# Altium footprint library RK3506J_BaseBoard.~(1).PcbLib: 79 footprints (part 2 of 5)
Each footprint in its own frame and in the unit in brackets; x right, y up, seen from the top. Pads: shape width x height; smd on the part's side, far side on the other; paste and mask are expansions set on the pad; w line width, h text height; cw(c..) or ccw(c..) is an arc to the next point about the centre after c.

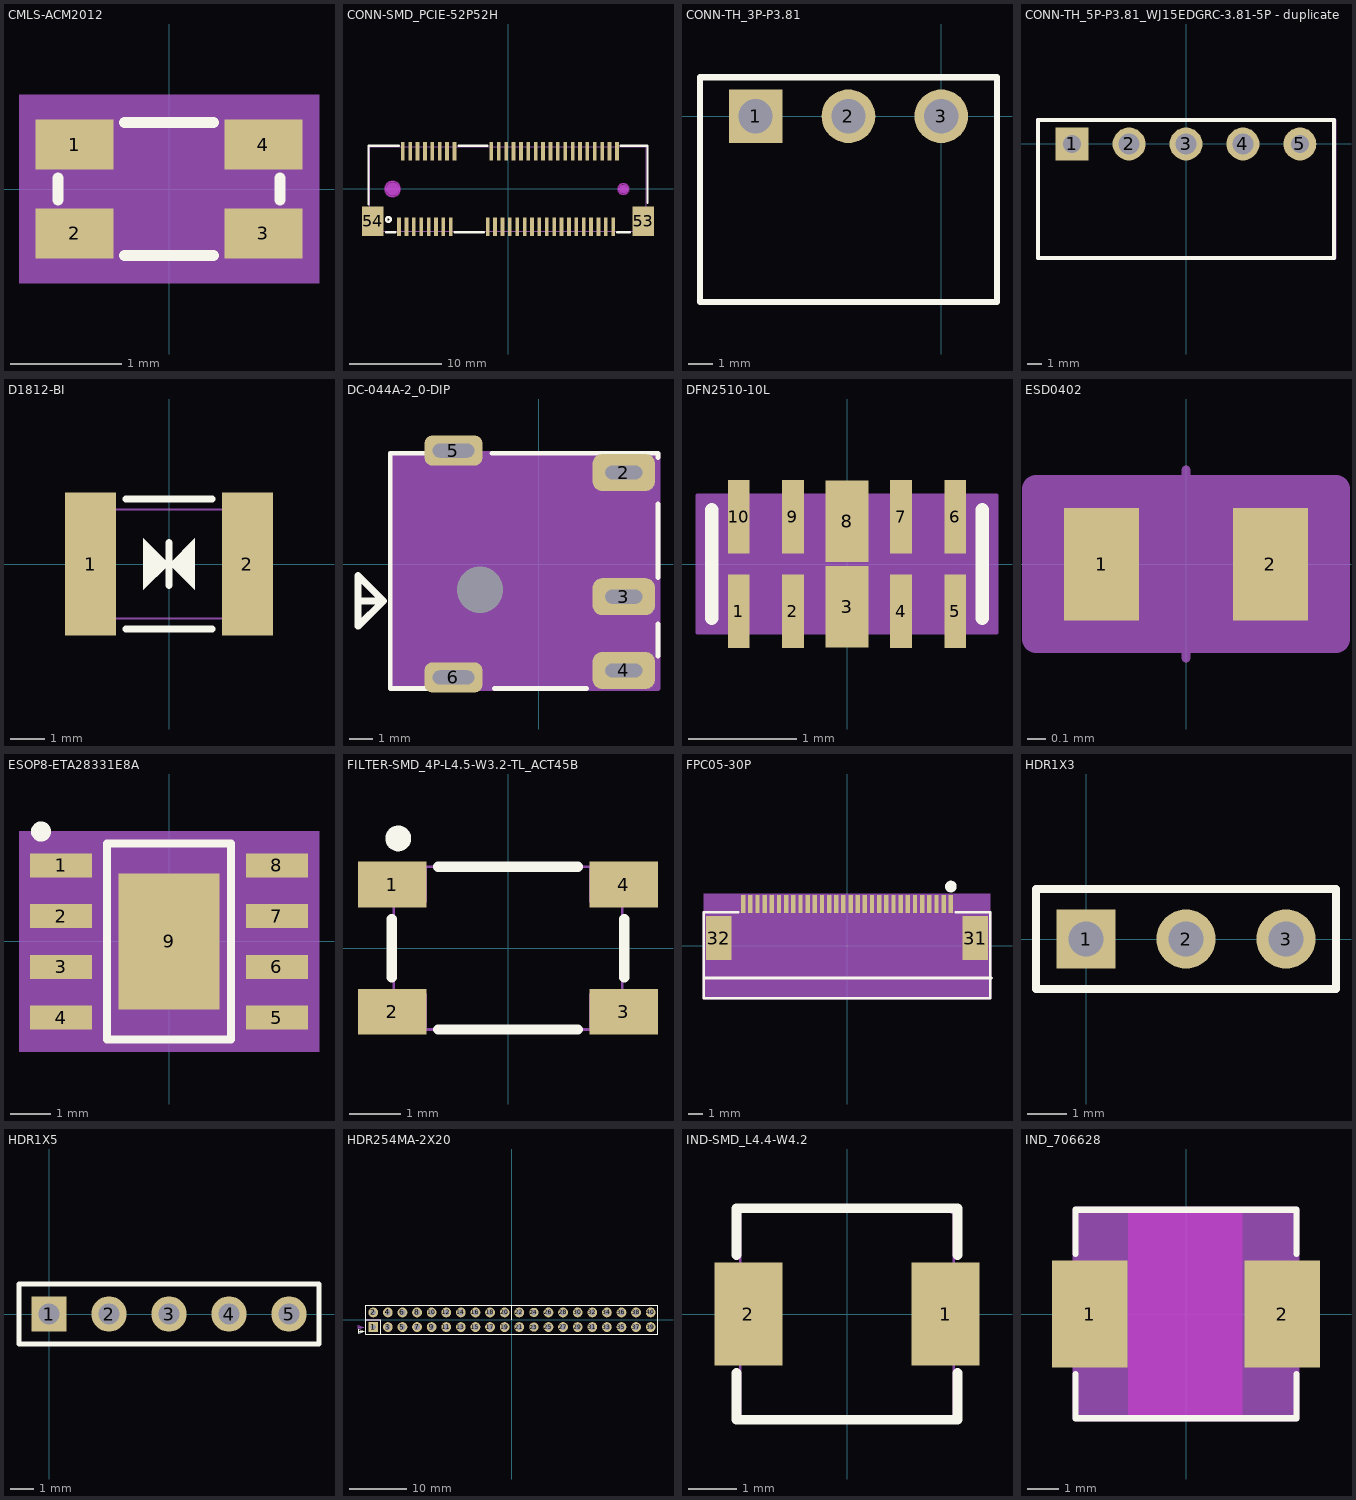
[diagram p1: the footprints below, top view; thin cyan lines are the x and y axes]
## CMLS-ACM2012 [mm]
pads (4):
  rect 0.7x0.45 smd: 1(-0.85,0.4) 2(-0.85,-0.4) 3(0.85,-0.4) 4(0.85,0.4)
Top Overlay:
  lines w0.1: -1,-0.1 -1,0.1 ; -0.4,-0.6 0.4,-0.6 ; -0.4,0.6 0.4,0.6 ; 1,-0.1 1,0.1
Top 3D Body:
  circle w0.05: c0,0 r0.35
  region: -1.35,-0.85 -1.35,0.85 1.35,0.85 1.35,-0.85
  lines w0.05: -0.5,0 0.5,0 ; 0,-0.5 0,0.5
Top Assembly:
  lines w0.1: -1,-0.6 -1,0.6 1,0.6 1,-0.6 -1,-0.6
Top Component Outline:
  lines w0.001: -1.1,-0.7 -1.1,0.7 1.1,0.7 1.1,-0.7 -1.1,-0.7
Top Courtyard:
  dashed: -1.35,-0.85 -1.35,0.85 1.35,0.85 1.35,-0.85
Mechanical 15:
  text "1" at -0.85,0.654 h0.76
  text "2" at -0.85,-0.146 h0.76
  text "3" at 0.85,-0.146 h0.76
  text "4" at 0.85,0.654 h0.76
3D body: height 3.81, standoff 0, extent -1.35,-0.85 1.35,0.85

## CONN-SMD_PCIE-52P52H [mm]
pads (54):
  rect 0.4x2 smd: 1(-11.8,-4.1) 2(-11.4,4.1) 3(-11,-4.1) 4(-10.6,4.1) 5(-10.2,-4.1) 6(-9.8,4.1) 7(-9.4,-4.1) 8(-9,4.1) 9(-8.6,-4.1) 10(-8.2,4.1) 11(-7.8,-4.1) 12(-7.4,4.1) 13(-7,-4.1) 14(-6.6,4.1) 15(-6.2,-4.1) 16(-5.8,4.1) 17(-2.2,-4.1) 18(-1.8,4.1) 19(-1.4,-4.1) 20(-1,4.1) 21(-0.6,-4.1) 22(-0.2,4.1) 23(0.2,-4.1) 24(0.6,4.1) 25(1,-4.1) 26(1.4,4.1) 27(1.8,-4.1) 28(2.2,4.1) 29(2.6,-4.1) 30(3,4.1) 31(3.4,-4.1) 32(3.8,4.1) 33(4.2,-4.1) 34(4.6,4.1) 35(5,-4.1) 36(5.4,4.1) 37(5.8,-4.1) 38(6.2,4.1) 39(6.6,-4.1) 40(7,4.1) 41(7.4,-4.1) 42(7.8,4.1) 43(8.2,-4.1) 44(8.6,4.1) 45(9,-4.1) 46(9.4,4.1) 47(9.8,-4.1) 48(10.2,4.1) 49(10.6,-4.1) 50(11,4.1) 51(11.4,-4.1) 52(11.8,4.1)
  rect 2.3x3.2 smd: 53(14.65,-3.5) 54(-14.65,-3.5)
Top Overlay:
  circle w0.254: c-12.954,-3.302 r0.254
  lines w0.254: -15.113,-1.651 -15.113,4.699 -11.831,4.699 ; -13.208,-4.699 -12.231,-4.699 ; -5.769,-4.699 -2.631,-4.699 ; -5.369,4.699 -2.231,4.699 ; 11.831,-4.699 13.208,-4.699 ; 12.231,4.699 15.113,4.699 15.113,-1.524
Keep-Out Layer:
  board cut-out: 13.05,0 13.05,0.11 12.966,0.312 12.811,0.466 12.609,0.55 12.39,0.55 12.188,0.466 12.034,0.312 11.95,0.109 11.95,0 11.95,-0.109 12.034,-0.311 12.188,-0.466 12.39,-0.55 12.609,-0.55 12.811,-0.466 12.966,-0.311 13.05,-0.109 13.05,0
  board cut-out: -11.7,0 -11.701,0.105 -11.756,0.308 -11.861,0.49 -12.01,0.638 -12.192,0.743 -12.395,0.797 -12.605,0.797 -12.808,0.743 -12.99,0.638 -13.139,0.49 -13.245,0.308 -13.3,0.105 -13.3,0 -13.3,-0.105 -13.245,-0.308 -13.139,-0.489 -12.99,-0.638 -12.808,-0.742 -12.605,-0.797 -12.395,-0.797 -12.192,-0.742 -12.01,-0.638 -11.861,-0.489 -11.756,-0.308 -11.701,-0.105 -11.7,0
Keep-Out Layer:
  circle w0.025: c12.5,0 r0.55
  circle w0.254: c12.5,0 r0.55
  circle w0.025: c-12.5,0 r0.8
  circle w0.254: c-12.5,0 r0.8
Mechanical 1:
  circle w0.025: c12.5,0 r0.55
  circle w0.025: c-12.5,0 r0.8
Top Component Outline:
  circle w0.7: c-12.5,0 r0.35
  circle w0.45: c12.5,0 r0.225
Mechanical 15:
  drawing of 59 lines, arcs and shapes, not listed

## CONN-TH_3P-P3.81 [mm]
pads (3):
  rect 2.2x2.2 hole 1.4: 1(-7.62,0)
  round 2.2 hole 1.4: 2(-3.81,0) 3(0,0)
Top Overlay:
  lines w0.254: -9.906,-7.62 -9.906,1.6 2.286,1.6 2.286,-7.62 -9.906,-7.62
Mechanical 15:
  region: -8.02,0.4 -7.22,0.4 -7.22,-0.4 -8.02,-0.4
  region: -4.21,0.4 -3.41,0.4 -3.41,-0.4 -4.21,-0.4
  region: -0.4,0.4 0.4,0.4 0.4,-0.4 -0.4,-0.4
  region: -9.905,-7.55 -9.906,-7.526 -9.941,-7.493 -9.989,-7.493 -10.024,-7.526 -10.025,-7.55 -10.024,-7.574 -9.989,-7.608 -9.941,-7.608 -9.906,-7.574 -9.905,-7.55
  lines w0.051: -9.965,-7.55 -9.965,1.651

## CONN-TH_5P-P3.81_WJ15EDGRC-3.81-5P - duplicate [mm]
pads (5):
  rect 2.2x2.2 hole 1.2: 1(-7.62,0)
  round 2.2 hole 1.4: 2(-3.81,0) 3(0,0) 4(3.81,0)
  round 2.2 hole 1.2: 5(7.62,0)
Top Overlay:
  lines w0.254: -9.906,-7.624 5.842,-7.624 9.906,-7.624 9.906,1.6 -9.906,1.6 -9.906,-7.55
Top Component Outline:
  region: 5.842,-7.497 9.779,-7.497 9.779,1.473 -9.779,1.473 -9.779,-7.55 -9.779,-7.603 -9.853,-7.677 -9.959,-7.677 -10.033,-7.603 -10.033,-7.55 -10.033,1.6 -10.033,1.625 -10.014,1.672 -9.978,1.708 -9.931,1.727 -9.906,1.727 9.906,1.727 9.931,1.727 9.978,1.708 10.014,1.672 10.033,1.625 10.033,1.6 10.033,-7.624 10.033,-7.649 10.014,-7.696 9.978,-7.732 9.931,-7.751 9.906,-7.751 5.842,-7.751 5.789,-7.751 5.715,-7.677 5.715,-7.571 5.789,-7.497 5.842,-7.497
  region: -9.906,-7.497 5.842,-7.497 5.895,-7.497 5.969,-7.571 5.969,-7.677 5.895,-7.751 5.842,-7.751 -9.906,-7.751 -9.959,-7.751 -10.033,-7.677 -10.033,-7.571 -9.959,-7.497 -9.906,-7.497
Mechanical 15:
  region: -9.905,-7.55 -9.906,-7.526 -9.941,-7.493 -9.989,-7.493 -10.024,-7.526 -10.025,-7.55 -10.024,-7.574 -9.989,-7.608 -9.941,-7.608 -9.906,-7.574 -9.905,-7.55
  region: 7.22,0.4 8.02,0.4 8.02,-0.4 7.22,-0.4
  region: 3.41,0.4 4.21,0.4 4.21,-0.4 3.41,-0.4
  region: -0.4,0.4 0.4,0.4 0.4,-0.4 -0.4,-0.4
  region: -4.21,0.4 -3.41,0.4 -3.41,-0.4 -4.21,-0.4
  region: -8.02,0.4 -7.22,0.4 -7.22,-0.4 -8.02,-0.4
  lines w0.051: -9.965,-7.55 -9.965,1.6 9.965,1.6 9.965,-7.55 -9.965,-7.55

## D1812-BI [mm]
pads (2):
  rect 1.5x4.2 smd: 1(-2.305,0) 2(2.305,0)
Top Overlay:
  region: 0,0 -0.762,-0.762 -0.762,0.762
  region: 0,0 0.762,0.762 0.762,-0.762
  lines w0.2: -1.27,-1.905 1.27,-1.905 ; -1.27,1.905 1.27,1.905 ; 0,-0.635 0,0.635
Mechanical 15:
  region: -2.25,1.6 -1.75,1.6 -1.75,-1.6 -2.25,-1.6
  region: 1.75,1.6 2.25,1.6 2.25,-1.6 1.75,-1.6
  region: -2.19,-1.6 -2.191,-1.576 -2.226,-1.542 -2.274,-1.542 -2.309,-1.576 -2.31,-1.6 -2.309,-1.624 -2.274,-1.658 -2.226,-1.658 -2.191,-1.624 -2.19,-1.6
  lines w0.051: -2.25,-1.6 2.25,-1.6 2.25,1.6 -2.25,1.6 -2.25,-1.6

## DC-044A-2_0-DIP [mm]
pads (6):
  round 0 / inner round 1.524 / far side round 2.3 hole 2 unplated: 1(-2.54,-1.115)
  rrect50% 2.7x1.6 hole 0.6 slot 1.6 at 0 deg: 2(3.69,3.965) 3(3.69,-1.415) 4(3.69,-4.615)
  rrect50% 2.5x1.3 hole 0.6 slot 1.8 at 0 deg: 5(-3.69,4.915) 6(-3.69,-4.915)
Top Overlay:
  lines w0.2: -4.928,4.803 -6.428,4.803 -6.428,-5.397 -4.828,-5.397 ; -2.028,4.803 5.172,4.803 5.172,4.602 ; -1.928,-5.397 2.072,-5.397 ; 5.172,-3.998 5.172,-2.598 ; 5.172,-0.598 5.172,2.602
  lines w0.3: -7.828,-1.598 -6.728,-1.598 ; -6.728,-1.598 -7.828,-0.498 -7.828,-2.698 -6.728,-1.598
Top 3D Body:
  region: -6.428,4.803 -6.428,-5.397 5.172,-5.397 5.172,4.803
Top Assembly:
  lines w0.2: -6.428,-5.397 -6.428,4.803 5.172,4.803 5.172,-5.397 -6.428,-5.397
  text "DC-044A-2_5" at -4.828,-3.898 h1.52
  text ".Designator" at 0.43,-0.582 h0.36
Mechanical 15:
  text "6" at -3.428,-5.613 h0.46
  text "5" at -3.428,4.186 h0.46
  text "2" at 3.772,3.236 h0.46
  text "3" at 3.772,-1.963 h0.46
  text "4" at 3.772,-5.364 h0.46
  text "1" at -2.328,-1.963 h0.46
3D body: height 3.81, standoff 0, extent -6.428,-5.397 5.172,4.803

## DFN2510-10L [mm]
pads (10):
  rect 0.2x0.68 smd: 1(-1,-0.437) 2(-0.5,-0.437) 4(0.5,-0.437) 5(1,-0.437) 6(1,0.437) 7(0.5,0.437) 9(-0.5,0.437) 10(-1,0.437)
  rect 0.4x0.75 smd: 3(0,-0.395) 8(0,0.395)
Top Overlay:
  lines w0.127: -1.25,-0.5 -1.25,0.5 ; 1.25,-0.5 1.25,0.5
Top 3D Body:
  region: -1.388,-0.637 1.388,-0.637 1.388,0.637 -1.388,0.637
Top Assembly:
  lines w0.025: -1.388,-0.637 -1.388,0.637 1.388,0.637 1.388,-0.637 -1.388,-0.637
Mechanical 15:
  text "3" at 0.142,-0.395 h0.36
  text "8" at 0.142,0.395 h0.36
  text "5" at 1.142,-0.437 h0.36
  text "6" at 1.142,0.437 h0.36
  text "4" at 0.642,-0.437 h0.36
  text "7" at 0.642,0.437 h0.36
  text "2" at -0.358,-0.437 h0.36
  text "9" at -0.358,0.437 h0.36
  text "1" at -0.858,-0.437 h0.36
  text "10" at -0.716,0.437 h0.36
3D body: height 3.81, standoff 0, extent -1.388,-0.637 1.388,0.637

## ESD0402 [mm]
pads (2):
  rect 0.4x0.6 smd: 1(-0.45,0) 2(0.45,0)
Top 3D Body:
  circle w0.05: c0,0 r0.35
  region: -0.8,0.4 -0.8,-0.4 0.8,-0.4 0.8,0.4
  lines w0.05: -0.5,0 0.5,0 ; 0,-0.5 0,0.5
Top Assembly:
  lines w0.15: -0.8,-0.4 -0.8,0.4 0.8,0.4 0.8,-0.4 -0.8,-0.4
Top Component Outline:
  lines w0.001: -0.525,-0.275 -0.525,0.275 0.525,0.275 0.525,-0.275 -0.525,-0.275
Mechanical 15:
  text "2" at 0.704,0 h0.76
  text "1" at -0.196,0 h0.76
3D body: height 3.81, standoff 0, extent -0.8,-0.4 0.8,0.4

## ESOP8-ETA28331E8A [mm]
pads (9):
  rect 1.55x0.6 smd: 1(-2.7,1.905) 2(-2.7,0.635) 3(-2.7,-0.635) 4(-2.7,-1.905) 5(2.7,-1.905) 6(2.7,-0.635) 7(2.7,0.635) 8(2.7,1.905)
  rect 2.513x3.402 smd: 9(0,0)
Top Overlay:
  circle w0.25: c-3.2,2.75 r0.125
  lines w0.2: -1.55,-2.45 1.55,-2.45 1.55,2.45 -1.55,2.45 -1.55,-2.45
Top 3D Body:
  circle w0.05: c0,0 r0.35
  region: -3.75,-2.75 -3.75,2.75 3.75,2.75 3.75,-2.75
  lines w0.05: -0.5,0 0.5,0 ; 0,-0.5 0,0.5
Top Assembly:
  circle w0.1: c-0.95,1.45 r0.5
  lines w0.1: -1.95,-2.45 1.95,-2.45 1.95,2.45 -1.95,2.45 -1.95,-2.45
Top Component Outline:
  lines w0.001: -2,-2.5 2,-2.5 2,2.5 -2,2.5 -2,-2.5
Top Courtyard:
  dashed: -3.75,-2.75 -3.75,2.75 3.75,2.75 3.75,-2.75
Mechanical 15:
  text "3" at -2.7,-0.889 h0.76
  text "4" at -2.7,-2.159 h0.76
  text "8" at 2.7,1.651 h0.76
  text "6" at 2.7,-0.889 h0.76
  text "1" at -2.7,1.651 h0.76
  text "5" at 2.7,-2.159 h0.76
  text "2" at -2.7,0.381 h0.76
  text "9" at 0,-0.254 h0.76
  text "7" at 2.7,0.381 h0.76
3D body: height 3.81, standoff 0, extent -3.75,-2.75 3.75,2.75

## FILTER-SMD_4P-L4.5-W3.2-TL_ACT45B [mm]
pads (4):
  rect 1.35x0.9 smd: 1(-2.275,1.25) 2(-2.275,-1.25) 3(2.275,-1.25) 4(2.275,1.25)
Top Overlay:
  circle w0.254: c-2.159,2.159 r0.127
  lines w0.203: -2.286,-0.569 -2.286,0.569 ; -1.369,-1.6 1.369,-1.6 ; -1.369,1.6 1.369,1.6 ; 2.286,-0.569 2.286,0.569
Mechanical 15:
  region: -2.25,0.9 -2.25,1.6 -1.6,1.6 -1.6,0.9
  region: 1.6,0.9 1.6,1.6 2.25,1.6 2.25,0.9
  region: 1.6,-1.6 1.6,-0.9 2.25,-0.9 2.25,-1.6
  region: -2.25,-1.6 -2.25,-0.9 -1.6,-0.9 -1.6,-1.6
  region: -2.19,1.6 -2.19,1.625 -2.225,1.66 -2.275,1.66 -2.31,1.625 -2.31,1.6 -2.31,1.575 -2.275,1.54 -2.225,1.54 -2.19,1.575 -2.19,1.6
  lines w0.051: -2.25,-1.6 2.25,-1.6 2.25,1.6 -2.25,1.6 -2.25,-1.6

## FPC05-30P [mm]
pads (32):
  rect 0.305x1.27 smd: 1(7.25,2.925) 2(6.75,2.925) 3(6.25,2.925) 4(5.75,2.925) 5(5.25,2.925) 6(4.75,2.925) 7(4.25,2.925) 8(3.75,2.925) 9(3.25,2.925) 10(2.75,2.925) 11(2.25,2.925) 12(1.75,2.925) 13(1.25,2.925) 14(0.75,2.925) 15(0.25,2.925) 16(-0.25,2.925) 17(-0.75,2.925) 18(-1.25,2.925) 19(-1.75,2.925) 20(-2.25,2.925) 21(-2.75,2.925) 22(-3.25,2.925) 23(-3.75,2.925) 24(-4.25,2.925) 25(-4.75,2.925) 26(-5.25,2.925) 27(-5.75,2.925) 28(-6.25,2.925) 29(-6.75,2.925) 30(-7.25,2.925)
  rect 1.803x3.048 smd: 31(8.95,0.55) 32(-8.95,0.55)
Top Overlay:
  circle w0.406: c7.25,4.147 r0.203
  lines w0.2: -10,-2.25 10.1,-2.25 ; -7.6,2.35 -10,2.35 -10,-3.65 10,-3.65 10,2.35 7.6,2.35
Top 3D Body:
  region: -10,-3.65 10,-3.65 10,3.65 -10,3.65
Top Assembly:
  lines w0.2: -10,-2.25 10,-2.25 ; -10,-3.65 10,-3.65 10,2.35 -10,2.35 -10,-3.65
Mechanical 15:
  text "30" at -7.25,2.417 h0.76
  text "32" at -8.95,0.042 h0.76
  text "23" at -3.75,2.417 h0.76
  text "24" at -4.25,2.417 h0.76
  text "19" at -1.75,2.417 h0.76
  text "20" at -2.25,2.417 h0.76
  text "21" at -2.75,2.417 h0.76
  text "22" at -3.25,2.417 h0.76
  text "13" at 1.25,2.417 h0.76
  text "16" at -0.25,2.417 h0.76
  text "31" at 8.95,0.042 h0.76
  text "6" at 4.75,2.671 h0.76
  text "4" at 5.75,2.671 h0.76
  text "10" at 2.75,2.417 h0.76
  text "8" at 3.75,2.671 h0.76
  text "12" at 1.75,2.417 h0.76
  text "11" at 2.25,2.417 h0.76
  text "15" at 0.25,2.417 h0.76
  text "18" at -1.25,2.417 h0.76
  text "17" at -0.75,2.417 h0.76
  text "14" at 0.75,2.417 h0.76
  text "1" at 7.25,2.671 h0.76
  text "2" at 6.75,2.671 h0.76
  text "3" at 6.25,2.671 h0.76
  text "29" at -6.75,2.417 h0.76
  text "9" at 3.25,2.671 h0.76
  text "7" at 4.25,2.671 h0.76
  text "28" at -6.25,2.417 h0.76
  text "25" at -4.75,2.417 h0.76
  text "27" at -5.75,2.417 h0.76
  text "26" at -5.25,2.417 h0.76
  text "5" at 5.25,2.671 h0.76
3D body: height 3.81, standoff 0, extent -10,-3.65 10,3.65

## HDR1X3 [mm]
pads (3):
  rect 1.5x1.5 hole 0.9: 1(0,0)
  round 1.5 hole 0.9: 2(2.54,0) 3(5.08,0)
Top Overlay:
  lines w0.2: -1.27,-1.27 6.35,-1.27 6.35,1.27 -1.27,1.27 -1.27,-1.27

## HDR1X5 [mm]
pads (5):
  rect 1.5x1.5 hole 0.9: 1(0,0)
  round 1.5 hole 0.9: 2(2.54,0) 3(5.08,0) 4(7.62,0) 5(10.16,0)
Top Overlay:
  lines w0.2: -1.27,-1.27 -1.27,1.27 11.43,1.27 11.43,-1.27 -1.27,-1.27

## HDR254MA-2X20 [mm]
pads (40):
  rect 1.7x1.7 / inner round 1.524 / far side rect 1.7x1.7 hole 0.9: 1(-24.13,-1.27)
  round 1.7 / inner round 1.524 / far side round 1.7 hole 0.9: 2(-24.13,1.27) 39(24.13,-1.27) 40(24.13,1.27)
  round 1.7 / inner round 1.524 / far side round 1.7 hole 1: 3(-21.59,-1.27) 4(-21.59,1.27) 5(-19.05,-1.27) 6(-19.05,1.27) 7(-16.51,-1.27) 8(-16.51,1.27) 9(-13.97,-1.27) 10(-13.97,1.27) 11(-11.43,-1.27) 13(-8.89,-1.27) 14(-8.89,1.27) 15(-6.35,-1.27) 16(-6.35,1.27) 17(-3.81,-1.27) 18(-3.81,1.27) 20(-1.27,1.27) 21(1.27,-1.27) 22(1.27,1.27) 25(6.35,-1.27) 26(6.35,1.27) 27(8.89,-1.27) 28(8.89,1.27) 29(11.43,-1.27) 31(13.97,-1.27) 32(13.97,1.27) 33(16.51,-1.27) 34(16.51,1.27) 35(19.05,-1.27) 36(19.05,1.27) 38(21.59,1.27)
  round 1.7 hole 1: 12(-11.43,1.27) 19(-1.27,-1.27) 30(11.43,1.27) 37(21.59,-1.27)
  round 1.6 / inner round 1.524 / far side round 1.7 hole 1: 23(3.81,-1.27) 24(3.81,1.27)
Top Overlay:
  lines w0.2: -26.654,-2.299 -25.654,-2.032 ; -26.654,-2.099 -25.654,-2.032 ; -26.654,-1.899 -25.654,-2.032 ; -25.4,0 -22.86,0 -22.86,-2.54 ; 0,0 0,2.54 ; -25.654,-2.032 -26.654,-1.699 -26.654,-2.365 -25.654,-2.032 ; -25.4,-2.54 -25.4,2.54 25.4,2.54 25.4,-2.54 -25.4,-2.54
Top 3D Body:
  lines w0.025: -25.4,-2.54 -25.4,2.54 25.4,2.54 25.4,-2.54 -25.4,-2.54
Top Assembly:
  lines w0.2: -26.781,-1.537 -25.781,-1.27 ; -26.781,-1.337 -25.781,-1.27 ; -26.781,-1.137 -25.781,-1.27 ; -25.4,0 -22.86,0 -22.86,-2.54 ; 0,0 0,2.54 ; -25.781,-1.27 -26.781,-0.937 -26.781,-1.603 -25.781,-1.27 ; -25.4,-2.54 -25.4,2.54 25.4,2.54 25.4,-2.54 -25.4,-2.54
  text "pn" at -24.45,-1.47 h0.76
Top Courtyard:
  lines w0.025: -25.4,-2.54 -25.4,2.54 25.4,2.54 25.4,-2.54 -25.4,-2.54
Mechanical 15:
  text "30" at 11.11,1.27 h0.4
  text "12" at -11.75,1.27 h0.4
  text "37" at 21.27,-1.27 h0.4
  text "19" at -1.59,-1.27 h0.4
  text "39" at 23.81,-1.27 h0.4
  text "40" at 23.81,1.27 h0.4
  text "24" at 3.49,1.27 h0.4
  text "26" at 6.03,1.27 h0.4
  text "4" at -21.75,1.27 h0.4
  text "6" at -19.21,1.27 h0.4
  text "8" at -16.67,1.27 h0.4
  text "10" at -14.29,1.27 h0.4
  text "11" at -11.75,-1.27 h0.4
  text "13" at -9.21,-1.27 h0.4
  text "15" at -6.67,-1.27 h0.4
  text "17" at -4.13,-1.27 h0.4
  text "14" at -9.21,1.27 h0.4
  text "21" at 0.95,-1.27 h0.4
  text "23" at 3.49,-1.27 h0.4
  text "25" at 6.03,-1.27 h0.4
  text "27" at 8.57,-1.27 h0.4
  text "22" at 0.95,1.27 h0.4
  text "29" at 11.11,-1.27 h0.4
  text "31" at 13.65,-1.27 h0.4
  text "33" at 16.19,-1.27 h0.4
  text "35" at 18.73,-1.27 h0.4
  text "32" at 13.65,1.27 h0.4
  text "18" at -4.13,1.27 h0.4
  text "20" at -1.59,1.27 h0.4
  text "3" at -21.75,-1.27 h0.4
  text "5" at -19.21,-1.27 h0.4
  text "7" at -16.67,-1.27 h0.4
  text "9" at -14.13,-1.27 h0.4
  text "38" at 21.27,1.27 h0.4
  text "36" at 18.73,1.27 h0.4
  text "34" at 16.19,1.27 h0.4
  text "28" at 8.57,1.27 h0.4
  text "16" at -6.67,1.27 h0.4
  text "2" at -24.29,1.27 h0.4
  text "1" at -24.29,-1.27 h0.4

## IND-SMD_L4.4-W4.2 [mm]
pads (2):
  rect 1.4x2.12 smd paste+0 mask+0.051: 1(2.028,0) 2(-2.028,0)
Top Overlay:
  lines w0.203: -2.276,-1.212 -2.276,-2.176 2.276,-2.176 2.276,-1.212 ; -2.276,1.212 -2.276,2.176 2.276,2.176 2.276,1.212
Mechanical 15:
  region: -2.2,1 -1.4,1 -1.4,-1 -2.2,-1
  region: 1.4,1 2.2,1 2.2,-1 1.4,-1
  region: 2.26,2.1 2.26,2.125 2.225,2.16 2.175,2.16 2.14,2.125 2.14,2.1 2.14,2.075 2.175,2.04 2.225,2.04 2.26,2.075 2.26,2.1
  lines w0.051: -2.2,-2.1 2.2,-2.1 2.2,2.1 -2.2,2.1 -2.2,-2.1

## IND_706628 [mm]
pads (2):
  rect 2.4x3.4 smd: 1(-3.05,0) 2(3.05,0)
Top Layer keep-out:
  region: -1.836,3.315 -1.836,-3.315 1.785,-3.315 1.785,3.315
Top Overlay:
  lines w0.2: -3.5,-1.9 -3.5,-3.3 3.5,-3.3 3.5,-1.9 ; -3.5,1.9 -3.5,3.3 3.5,3.3 3.5,1.9
Top 3D Body:
  region: -3.5,-3.3 3.5,-3.3 3.5,3.3 -3.5,3.3
Top Assembly:
  lines w0.2: -3.5,-3.3 -3.5,3.3 3.5,3.3 3.5,-3.3 -3.5,-3.3
Mechanical 15:
  text "1" at -3.05,0.254 h0.64
  text "2" at 3.05,0.254 h0.64
3D body: height 3.81, standoff 0, extent -3.5,-3.3 3.5,3.3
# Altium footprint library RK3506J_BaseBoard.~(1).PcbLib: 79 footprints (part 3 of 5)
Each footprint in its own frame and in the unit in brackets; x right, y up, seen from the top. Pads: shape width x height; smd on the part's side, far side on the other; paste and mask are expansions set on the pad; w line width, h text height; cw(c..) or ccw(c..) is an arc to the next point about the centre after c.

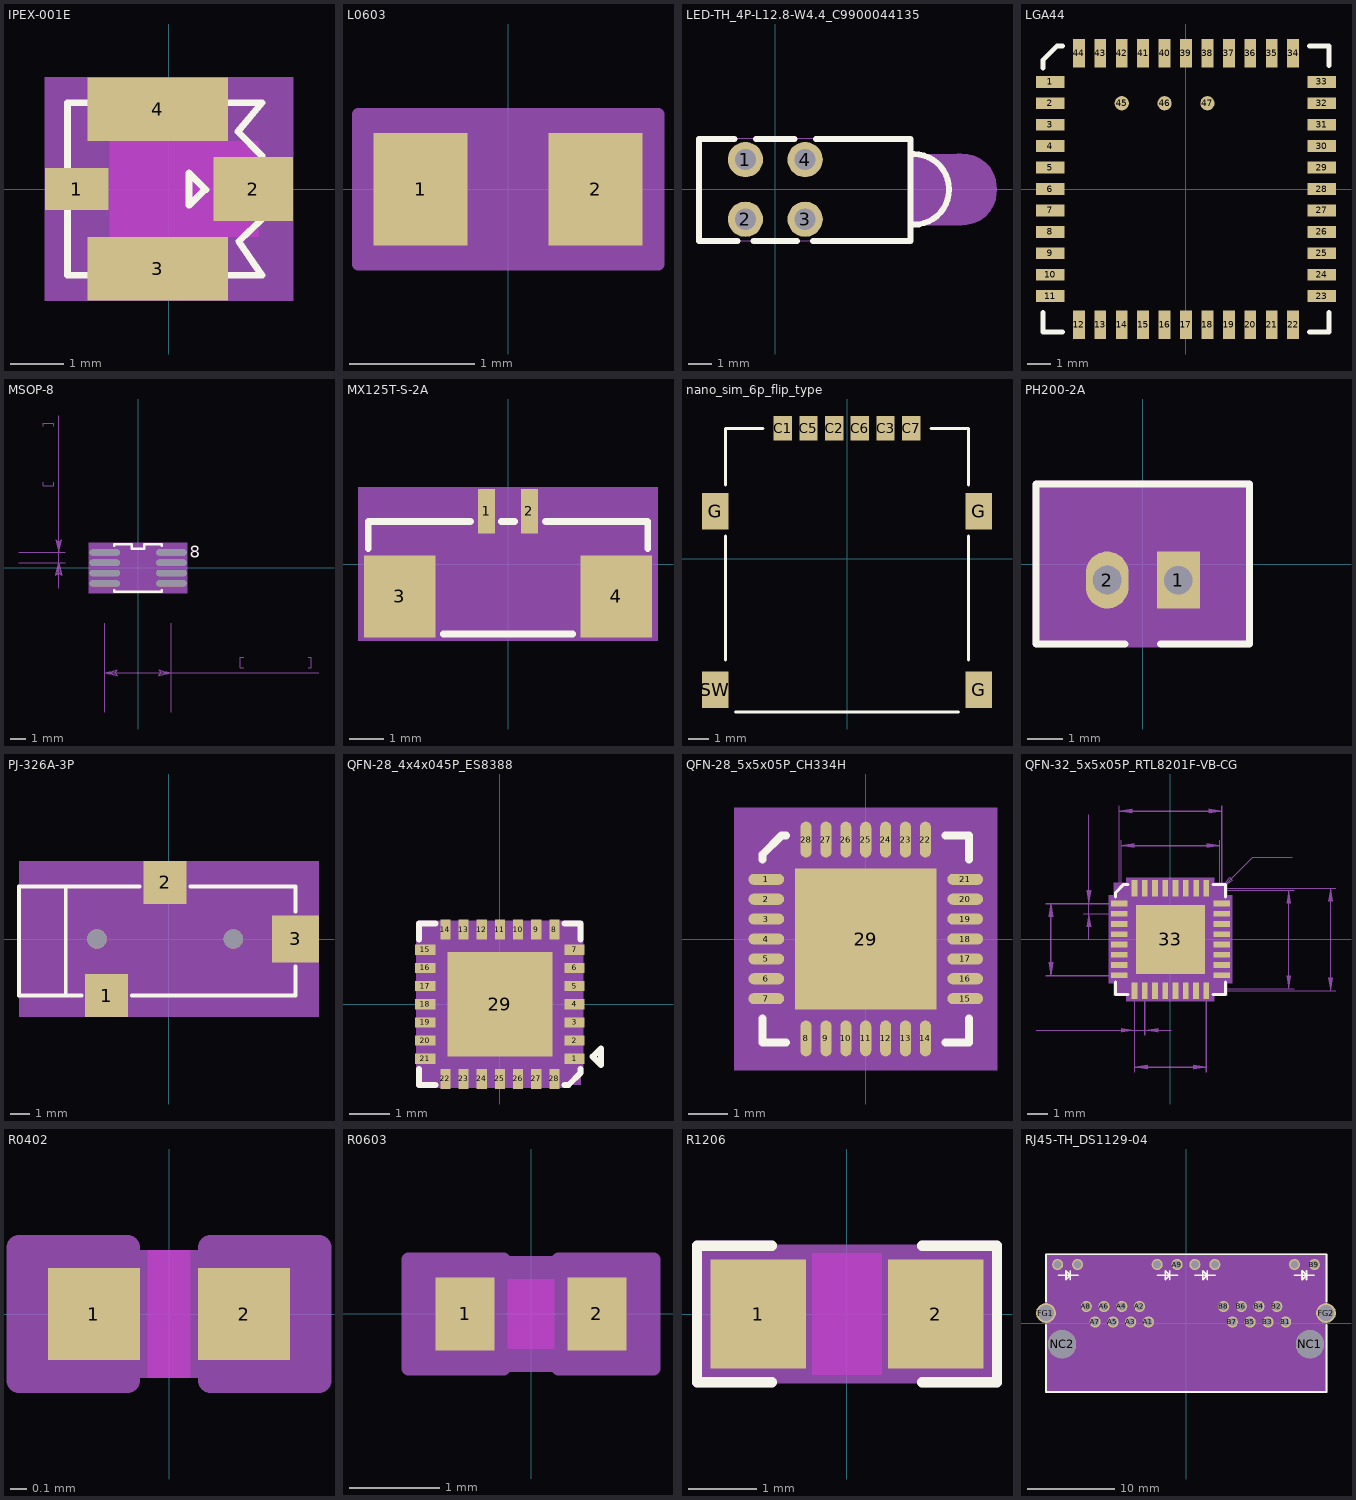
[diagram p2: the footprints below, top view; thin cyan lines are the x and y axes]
## IPEX-001E [mm]
pads (4):
  rect 1.2x0.8 smd: 1(-1.737,0)
  rect 1.5x1.2 smd: 2(1.587,0)
  rect 2.65x1.2 smd: 3(-0.212,-1.5) 4(-0.212,1.5)
Top Layer keep-out:
  region: 1.687,0.9 -1.112,0.9 -1.112,-0.9 1.687,-0.9
Top Overlay:
  lines w0.127: 0.658,-0.029 0.379,-0.308 0.379,0.302 0.696,-0.016 0.658,-0.016 ; -1.912,-1.625 -1.912,1.625 1.751,1.625 1.297,1.079 1.751,0.625 1.751,-0.564 1.314,-0.985 1.751,-1.625 -1.912,-1.625
Top 3D Body:
  region: -2.337,-2.1 2.338,-2.1 2.338,2.1 -2.337,2.1
Top Assembly:
Mechanical 15:
  text "2" at 1.841,0 h0.76
  text "4" at 0.042,1.5 h0.76
  text "1" at -1.483,0 h0.76
  text "3" at 0.042,-1.5 h0.76
3D body: height 3.81, standoff 0, extent -2.337,-2.1 2.338,2.1

## L0603 [mm]
pads (2):
  rect 0.75x0.9 smd: 1(-0.7,0) 2(0.7,0)
Top 3D Body:
  circle w0.05: c0,0 r0.35
  region: -1.2,-0.6 -1.2,0.6 1.2,0.6 1.2,-0.6
  lines w0.05: -0.5,0 0.5,0 ; 0,-0.5 0,0.5
Top Assembly:
  lines w0.1: -0.2,-0.4 0.2,-0.1 -0.2,0.2 0.2,0.5 ; -1.2,-0.6 -1.2,0.6 1.2,0.6 1.2,-0.6 -1.2,-0.6
Top Component Outline:
  lines w0.001: -0.875,-0.475 -0.875,0.475 0.875,0.475 0.875,-0.475 -0.875,-0.475
Top Courtyard:
  dashed: -1.2,-0.6 -1.2,0.6 1.2,0.6 1.2,-0.6
Mechanical 15:
  text "1" at -0.954,0 h0.76
  text "2" at 0.446,0 h0.76
3D body: height 3.81, standoff 0, extent -1.2,-0.6 1.2,0.6

## LED-TH_4P-L12.8-W4.4_C9900044135 [mm]
pads (4):
  round 1.5 hole 0.9 paste+0 mask+0.05: 1(-1.27,1.27) 2(-1.27,-1.27) 3(1.27,-1.27) 4(1.27,1.27)
Top Overlay:
  lines w0.254: -1.727,2.15 -3.25,2.15 -3.25,-2.2 -1.614,-2.2 ; -0.926,-2.2 0.926,-2.2 ; -0.813,2.15 0.813,2.15 ; 1.614,-2.2 5.75,-2.2 5.75,-1.5 5.751,1.501 5.751,2.149 1.727,2.149 ; 5.9,-1.5 ccw(c5.894,0.001) 5.9,1.501
Top Component Outline:
  region: 5.75,-1.5 8,-1.5 8.144,-1.5 8.427,-1.442 8.692,-1.327 8.928,-1.161 9.126,-0.95 9.275,-0.703 9.372,-0.43 9.41,-0.144 9.4,0 9.41,0.141 9.374,0.421 9.282,0.689 9.139,0.932 8.95,1.142 8.722,1.31 8.466,1.43 8.191,1.495 8.05,1.5 5.75,1.5
Mechanical 15:
  region: -3.21,2.175 -3.21,2.2 -3.245,2.235 -3.295,2.235 -3.33,2.2 -3.33,2.175 -3.33,2.15 -3.295,2.115 -3.245,2.115 -3.21,2.15 -3.21,2.175
  region: -1.52,1.02 -1.52,1.52 -1.02,1.52 -1.02,1.02
  region: -1.52,-1.52 -1.52,-1.02 -1.02,-1.02 -1.02,-1.52
  region: 1.02,-1.52 1.02,-1.02 1.52,-1.02 1.52,-1.52
  region: 1.02,1.02 1.02,1.52 1.52,1.52 1.52,1.02
  lines w0.051: 5.73,1.5 7.73,1.5 cw(c7.833,-0.097) 9.43,0 cw(c7.833,0.097) 7.73,-1.5 5.73,-1.5 5.73,-2.175 -3.27,-2.175 -3.27,2.175 5.73,2.175 5.73,1.5 ; 5.73,1.5 5.73,1.5

## LGA44 [mm]
pads (47):
  rect 1.2x0.5 smd: 1(-5.7,4.5) 2(-5.7,3.6) 3(-5.7,2.7) 4(-5.7,1.8) 5(-5.7,0.9) 6(-5.7,0) 7(-5.7,-0.9) 8(-5.7,-1.8) 9(-5.7,-2.7) 10(-5.7,-3.6) 11(-5.7,-4.5) 23(5.7,-4.5) 24(5.7,-3.6) 25(5.7,-2.7) 26(5.7,-1.8) 27(5.7,-0.9) 28(5.7,0) 29(5.7,0.9) 30(5.7,1.8) 31(5.7,2.7) 32(5.7,3.6) 33(5.7,4.5)
  rect 0.5x1.2 smd: 12(-4.5,-5.7) 13(-3.6,-5.7) 14(-2.7,-5.7) 15(-1.8,-5.7) 16(-0.9,-5.7) 17(0,-5.7) 18(0.9,-5.7) 19(1.8,-5.7) 20(2.7,-5.7) 21(3.6,-5.7) 22(4.5,-5.7) 34(4.5,5.7) 35(3.6,5.7) 36(2.7,5.7) 37(1.8,5.7) 38(0.9,5.7) 39(0,5.7) 40(-0.9,5.7) 41(-1.8,5.7) 42(-2.7,5.7) 43(-3.6,5.7) 44(-4.5,5.7)
  round 0.6 smd: 45(-2.7,3.6) 46(-0.9,3.6) 47(0.9,3.6)
Top Overlay:
  lines w0.203: -6,-5.176 -6,-6 -5.176,-6 ; -6,5.08 -6,5.43 -5.43,6 -5.176,6 ; 5.176,-6 6,-6 6,-5.176 ; 5.176,6 6,6 6,5.176
Mechanical 14:
  text "'.Designator'" at -0.508,2.286 h1

## MSOP-8 [mil]
pads (8):
  oval 75x15 smd: 1(-82.68,38.39) 2(-82.68,12.8) 3(-82.68,-12.8) 4(-82.68,-38.39) 5(82.68,-38.39) 6(82.68,-12.8) 7(82.68,12.8) 8(82.68,38.39)
Top Overlay:
  lines w5.91: -59.06,-55.12 -59.06,-59.06 59.06,-59.06 59.06,-55.12 ; -59.06,55.12 -59.06,59.06 -15.75,59.06 -15.75,47.24 15.75,47.24 15.75,59.06 59.06,59.06 59.06,55.12
  text "8" at 127.9,25.6 h30
Top Solder:
  dashed: 48.03,46.06 107.87,46.06 120.08,46.06 120.08,-46.06 107.87,-46.06 48.03,-46.06 45.28,-46.06 45.28,46.06
  dashed: -117.32,46.06 -57.48,46.06 -45.28,46.06 -45.28,-46.06 -57.48,-46.06 -117.32,-46.06 -120.08,-46.06 -120.08,46.06
Top 3D Body:
  region: 122.05,59.05 122.05,-55.12 122.05,-62.99 -122.05,-62.99 -122.05,-55.12 -122.05,59.06 -122.05,62.99 122.05,62.99
Top Assembly:
  lines w5.91: -59.06,-59.06 59.06,-59.06 59.06,59.06 -59.06,59.06 -59.06,-59.06
Top Component Center:
  circle w1: c0,0 r13.39
  lines w1: -20.08,0 20.08,0 ; 0,-20.08 0,20.08
Mechanical 15:
  text "2" at -82.68,2.8 h30
  text "6" at 82.68,-22.8 h30
  text "1" at -82.68,28.39 h30
  text "5" at 82.68,-48.39 h30
  text "8" at 82.68,28.39 h30
  text "4" at -82.68,-48.39 h30
  text "3" at -82.68,-22.8 h30
  text "7" at 82.68,2.8 h30
Mechanical 26:
  lines w1: -295.28,12.8 -181.1,12.8 ; -295.28,38.39 -181.1,38.39 ; -234.65,212.2 -234.65,204.13 -209.45,204.13 -209.45,212.2 ; -234.65,350.79 -234.65,358.86 -209.45,358.86 -209.45,350.79 ; -196.85,-50.2 -196.85,12.8 ; -196.85,377.76 -196.85,38.39 ; -82.68,-358.27 -82.68,-136.81 ; 82.68,-358.27 82.68,-136.81 ; 261.81,-247.24 253.74,-247.24 253.74,-222.05 261.81,-222.05 ; 421.65,-247.24 429.72,-247.24 429.72,-222.05 421.65,-222.05 ; 448.62,-259.84 82.68,-259.84 ; -204.72,69.88 -200.79,66.73 -196.85,38.39 ; -204.72,69.88 -196.85,63.58 ; -204.72,69.88 -196.85,38.39 ; -196.85,-12.4 -196.85,12.8 ; -196.85,-12.4 -200.79,-15.55 -196.85,12.8 ; -196.85,-12.4 -188.98,-18.7 ; -196.85,-12.4 -204.72,-18.7 -196.85,12.8 ; -196.85,12.8 -196.85,38.39 ; -196.85,12.8 -192.91,-15.55 -188.98,-18.7 ; -196.85,12.8 -188.98,-18.7 ; -196.85,38.39 -196.85,63.58 ; -196.85,38.39 -192.91,66.73 -196.85,63.58 ; -196.85,38.39 -188.98,69.88 -196.85,63.58 ; -82.68,-259.84 82.68,-259.84 ; -82.68,-259.84 -54.33,-255.91 -51.18,-251.97 ; -82.68,-259.84 -57.48,-259.84 ; -82.68,-259.84 -54.33,-263.78 -57.48,-259.84 ; -82.68,-259.84 -51.18,-267.72 -57.48,-259.84 ; -82.68,-259.84 -51.18,-251.97 ; -82.68,-259.84 82.68,-259.84 ; -57.48,-259.84 -51.18,-251.97 ; 51.18,-267.72 54.33,-263.78 82.68,-259.84 ; 51.18,-267.72 57.48,-259.84 ; 51.18,-267.72 82.68,-259.84 ; 57.48,-259.84 82.68,-259.84 ; 57.48,-259.84 54.33,-255.91 82.68,-259.84 ; 57.48,-259.84 51.18,-251.97 82.68,-259.84
  text "165.354" at 269.88,-247.24 h25
  text "4.2" at 160.83,-247.24 h25
  text "25.591" at -209.45,220.28 h25
  text "0.65" at -209.45,89.96 h25
  text "VER1 AUGUST 16,2007" at 38.98,216.54 h25
3D body: height 150, standoff 0, extent -122.05,-62.99 122.05,62.99

## MX125T-S-2A [mm]
pads (4):
  rect 0.5x1.3 smd: 1(-0.625,1.55) 2(0.625,1.55)
  rect 2.1x2.4 smd: 3(-3.175,-0.95) 4(3.175,-0.95)
Top Overlay:
  lines w0.2: -4.1,0.45 -4.1,1.25 -1.1,1.25 ; -1.9,-2.05 1.9,-2.05 ; -0.2,1.25 0.2,1.25 ; 1.1,1.25 4.1,1.25 4.1,0.45
Top 3D Body:
  region: 4.4,2.25 -4.175,2.25 -4.3,2.25 -4.4,2.25 -4.4,-2.25 -4.3,-2.25 -4.275,-2.25 -4.25,-2.25 -4.125,-2.25 -4,-2.25 4.4,-2.25
Top Assembly:
  lines w0.2: -4.1,-2.05 -4.1,1.25 4.1,1.25 4.1,-2.05 -4.1,-2.05
Mechanical 15:
  text "2" at 0.523,1.55 h0.25
  text "1" at -0.726,1.55 h0.25
  text "3" at -3.277,-0.95 h0.25
  text "4" at 3.074,-0.95 h0.25
3D body: height 3.81, standoff 0, extent -4.4,-2.25 4.4,2.25

## nano_sim_6p_flip_type [mm]
pads (10):
  rect 0.9x1.2 smd mask+0.051: C1(-3.175,6.45) C2(-0.635,6.45) C3(1.905,6.45) C5(-1.905,6.45) C6(0.635,6.45) C7(3.175,6.45)
  rect 1.3x1.8 smd mask+0.051: G(-6.505,2.35) G(6.505,-6.45) G(6.505,2.35) SW(-6.505,-6.45)
Top Overlay:
  lines w0.152: -5.997,-5 -5.997,1.115 ; -5.997,3.655 -5.997,6.444 -4.158,6.444 ; -5.5,-7.556 5.5,-7.556 ; 4.158,6.444 6.003,6.444 6.003,3.649 ; 5.997,-5 5.997,1.115

## PH200-2A [mm]
pads (2):
  rect 1.2x1.6 / inner round 1.524 / far side rect 1.2x1.6 hole 0.8: 1(1,-0.45)
  oval 1.2x1.6 / inner round 1.524 / far side oval 1.2x1.6 hole 0.8: 2(-1,-0.45)
Top Overlay:
  lines w0.2: -0.5,-2.25 -3,-2.25 -3,2.25 3,2.25 3,-2.25 0.5,-2.25
Top 3D Body:
  region: -3,2.25 -3,-2.25 3,-2.25 3,2.25
Top Assembly:
  lines w0.2: -3,-2.25 3,-2.25 3,2.25 -3,2.25 -3,-2.25
Mechanical 15:
  text "2" at -0.262,-0.75 h0.76
  text "1" at 1.738,-0.75 h0.76
3D body: height 3.81, standoff 0, extent -3,-2.25 3,2.25

## PJ-326A-3P [mm]
pads (5):
  rect 2.2x2.2 smd: 1(-3.2,-2.9) 2(-0.2,2.901)
  rect 2.4x2.4 smd: 3(6.5,0.001)
  round 1 hole 1: ""(-3.7,0.001) ""(3.3,0.001)
Top Overlay:
  lines w0.2: -5.3,-2.9 -5.3,2.7 ; -4.5,-2.9 -7.7,-2.9 -7.7,2.7 -1.5,2.7 ; -1.9,-2.9 6.5,-2.9 6.5,-1.4 ; 1.1,2.7 6.5,2.7 6.5,1.4
Top 3D Body:
  region: -7.7,-4 -7.7,4 7.7,4 7.7,-4
Top Assembly:
  lines w0.2: -5.3,-2.9 -5.3,2.7 ; -5.3,2.7 6.5,2.7 6.5,-2.9 -7.7,-2.9 -7.7,2.7 -5.3,2.7
Mechanical 15:
  text "2" at -0.2,2.536 h0.91
  text "3" at 6.5,-0.365 h0.91
  text "1" at -3.2,-3.266 h0.91
3D body: height 3.81, standoff 0, extent -7.7,-4 7.7,4

## QFN-28_4x4x045P_ES8388 [mm]
pads (29):
  rect 0.5x0.25 smd: 1(1.85,-1.35) 2(1.85,-0.9) 3(1.85,-0.45) 4(1.85,0) 5(1.85,0.45) 6(1.85,0.9) 7(1.85,1.35) 15(-1.85,1.35) 16(-1.85,0.9) 17(-1.85,0.45) 18(-1.85,0) 19(-1.85,-0.45) 20(-1.85,-0.9) 21(-1.85,-1.35)
  rect 0.25x0.5 smd: 8(1.35,1.85) 9(0.9,1.85) 10(0.45,1.85) 11(0,1.85) 12(-0.45,1.85) 13(-0.9,1.85) 14(-1.35,1.85) 22(-1.35,-1.85) 23(-0.9,-1.85) 24(-0.45,-1.85) 25(0,-1.85) 26(0.45,-1.85) 27(0.9,-1.85) 28(1.35,-1.85)
  rect 2.601x2.601 smd: 29(0,0)
Top Overlay:
  lines w0.15: -2,-1.6 -2,-2 -1.6,-2 ; -2,1.6 -2,2 -1.6,2 ; 1.6,-2 1.7,-2 2,-1.7 2,-1.6 ; 1.6,2 2,2 2,1.6 ; 2.3,-1.3 2.5,-1.1 2.5,-1.5 2.3,-1.3
Top 3D Body:
  region: 2,2 2,-2 -2,-2 -2,2
Top Assembly:
  lines w0.15: -2,-2 1.7,-2 2,-1.7 2,2 -2,2 -2,-2
Top Courtyard:
  dashed: 2,2 2,-2 -2,-2 -2,2
Mechanical 15:
  text "1" at 1.647,-1.35 h0.51
  text "21" at -2.256,-1.35 h0.51
  text "22" at -1.756,-1.85 h0.51
  text "16" at -2.256,0.9 h0.51
  text "3" at 1.647,-0.45 h0.51
  text "2" at 1.647,-0.9 h0.51
  text "17" at -2.256,0.45 h0.51
  text "27" at 0.494,-1.85 h0.51
  text "13" at -1.306,1.85 h0.51
  text "14" at -1.756,1.85 h0.51
  text "15" at -2.256,1.35 h0.51
  text "6" at 1.647,0.9 h0.51
  text "8" at 1.147,1.85 h0.51
  text "10" at 0.044,1.85 h0.51
  text "7" at 1.647,1.35 h0.51
  text "19" at -2.256,-0.45 h0.51
  text "5" at 1.647,0.45 h0.51
  text "24" at -0.856,-1.85 h0.51
  text "23" at -1.306,-1.85 h0.51
  text "12" at -0.856,1.85 h0.51
  text "20" at -2.256,-0.9 h0.51
  text "26" at 0.044,-1.85 h0.51
  text "11" at -0.406,1.85 h0.51
  text "28" at 0.944,-1.85 h0.51
  text "29" at -0.813,0 h0.51
  text "18" at -2.256,0 h0.51
  text "4" at 1.647,0 h0.51
  text "9" at 0.697,1.85 h0.51
  text "25" at -0.406,-1.85 h0.51
3D body: height 3.81, standoff 0, extent -2,-2 2,2

## QFN-28_5x5x05P_CH334H [mm]
pads (29):
  oval 0.899x0.279 smd: 1(-2.5,1.5) 2(-2.5,1) 3(-2.5,0.5) 4(-2.5,0) 5(-2.5,-0.5) 6(-2.5,-1) 7(-2.5,-1.5) 15(2.5,-1.5) 16(2.5,-1) 17(2.5,-0.5) 18(2.5,0) 19(2.5,0.5) 20(2.5,1) 21(2.5,1.5)
  oval 0.279x0.899 smd: 8(-1.5,-2.5) 9(-1,-2.5) 10(-0.5,-2.5) 11(0,-2.5) 12(0.5,-2.5) 13(1,-2.5) 14(1.5,-2.5) 22(1.5,2.5) 23(1,2.5) 24(0.5,2.5) 25(0,2.5) 26(-0.5,2.5) 27(-1,2.5) 28(-1.5,2.5)
  rect 3.55x3.55 smd: 29(0,0)
Top Overlay:
  lines w0.2: -2.6,-2 -2.6,-2.6 -2,-2.6 ; -2.6,2 -2.6,2.12 -2.12,2.6 -2,2.6 ; 2,-2.6 2.6,-2.6 2.6,-2 ; 2,2.6 2.6,2.6 2.6,2
Top Paste:
  dashed: -1.154,1.154 1.154,1.154 1.154,-1.154 -1.154,-1.154
Top 3D Body:
  circle w0.05: c0,0 r0.35
  region: -3.3,-3.3 -3.3,3.3 3.3,3.3 3.3,-3.3
  lines w0.05: -0.5,0 0.5,0 ; 0,-0.5 0,0.5
Top Assembly:
  circle w0.1: c-1.575,1.575 r0.5
  lines w0.1: -2.575,-2.575 -2.575,2.575 2.575,2.575 2.575,-2.575 -2.575,-2.575
Top Component Outline:
  lines w0.001: -2.65,-2.65 -2.65,2.65 2.65,2.65 2.65,-2.65 -2.65,-2.65
Top Courtyard:
  dashed: -3.3,-3.3 -3.3,3.3 3.3,3.3 3.3,-3.3
Mechanical 15:
  text "18" at 2.042,0 h0.76
  text "29" at -0.508,0 h0.76
  text "16" at 2.042,-1 h0.76
  text "1" at -2.804,1.5 h0.76
  text "21" at 2.042,1.5 h0.76
  text "17" at 2.042,-0.5 h0.76
  text "19" at 2.042,0.5 h0.76
  text "20" at 2.042,1 h0.76
3D body: height 3.81, standoff 0, extent -3.3,-3.3 3.3,3.3

## QFN-32_5x5x05P_RTL8201F-VB-CG [mil]
pads (33):
  rect 31.5x11 smd: 1(-98.43,68.9) 2(-98.43,49.25) 3(-98.43,29.57) 4(-98.43,9.88) 5(-98.43,-9.8) 6(-98.43,-29.49) 7(-98.43,-49.17) 8(-98.43,-68.86) 17(98.43,-68.9) 18(98.43,-49.25) 19(98.43,-29.57) 20(98.43,-9.88) 21(98.43,9.8) 22(98.43,29.49) 23(98.43,49.17) 24(98.43,68.86)
  rect 11x31.5 smd: 9(-68.9,-98.43) 10(-49.25,-98.43) 11(-29.57,-98.43) 12(-9.88,-98.43) 13(9.8,-98.43) 14(29.49,-98.43) 15(49.17,-98.43) 16(68.86,-98.43) 25(68.9,98.43) 26(49.25,98.43) 27(29.57,98.43) 28(9.88,98.43) 29(-9.8,98.43) 30(-29.49,98.43) 31(-49.17,98.43) 32(-68.86,98.43)
  rect 131.89x131.89 smd: 33(0,0)
Top Overlay:
  lines w6: -105.51,-81.46 -105.51,-105.51 -81.46,-105.51 ; -105.51,81.46 -105.51,89.76 -89.76,105.51 -81.46,105.51 ; 81.46,-105.51 105.51,-105.51 105.51,-81.46 ; 81.46,105.51 105.51,105.51 105.51,81.46
Top Paste:
  dashed: -60,-30 -60,-60 -30,-60 -30,-30
  dashed: -60,15 -60,-15 -30,-15 -30,15
  dashed: -15,15 -15,-15 15,-15 15,15
  dashed: -15,-30 -15,-60 15,-60 15,-30
  dashed: 30,-30 30,-60 60,-60 60,-30
  dashed: 30,15 30,-15 60,-15 60,15
  dashed: 30,60 30,30 60,30 60,60
  dashed: -15,60 -15,30 15,30 15,60
  dashed: -60,60 -60,30 -30,30 -30,60
Top 3D Body:
  region: -74.45,-108.5 74.45,-108.5 74.45,-98.5 98.5,-98.5 98.5,-74.45 108.5,-74.45 108.5,74.45 98.5,74.45 98.5,98.5 74.45,98.5 74.45,108.5 -74.45,108.5 -74.45,98.5 -98.5,98.5 -98.5,74.45 -108.5,74.45 -108.5,-74.45 -98.5,-74.45 -98.5,-98.5 -74.45,-98.5
Top Assembly:
  lines w6: -98.5,-98.5 -98.5,82.75 -82.75,98.5 98.5,98.5 98.5,-98.5 -98.5,-98.5
Top Component Outline:
  dashed: -73.5,250.41 -98.5,246.42 -73.5,242.42
  dashed: 73.5,242.42 98.5,246.42 73.5,250.41
  dashed: 303.08,-73.5 307.08,-98.5 311.07,-73.5
  dashed: 311.07,73.5 307.08,98.5 303.08,73.5
  dashed: -69.5,184.32 -94.5,180.33 -69.5,176.33
  dashed: 69.5,176.33 94.5,180.33 69.5,184.32
  dashed: 222.77,-69.5 226.76,-94.5 230.76,-69.5
  dashed: 230.76,69.5 226.76,94.5 222.77,69.5
  dashed: -43.95,-240.64 -68.95,-244.63 -43.95,-248.63
  dashed: 43.95,-248.63 68.95,-244.63 43.95,-240.64
  dashed: -93.95,-177.97 -68.95,-173.97 -93.95,-169.98
  dashed: -24.25,-169.98 -49.25,-173.97 -24.25,-177.97
  dashed: -233.48,-43.95 -229.49,-68.95 -225.49,-43.95
  dashed: -225.49,43.95 -229.49,68.95 -233.48,43.95
  dashed: -152.81,24.25 -156.81,49.25 -160.81,24.25
  dashed: -160.81,93.95 -156.81,68.95 -152.81,93.95
  lines w1: -257.88,-173.97 -68.95,-173.97 -49.25,-173.97 0.75,-173.97 ; -239.49,-68.95 -104.5,-68.95 ; -239.49,68.95 -104.5,68.95 -166.81,68.95 ; -229.49,-68.95 -229.49,2.33 -229.49,68.95 ; -166.81,49.25 -104.5,49.25 ; -156.81,-0.75 -156.81,49.25 -156.81,68.95 -156.81,239.33 ; -98.5,108.5 -98.5,256.42 ; -98.5,246.42 2.02,246.42 98.5,246.42 ; -94.5,78.95 -94.5,190.33 ; -94.5,180.33 -0.69,180.33 94.5,180.33 ; -68.95,-254.63 -68.95,-104.5 -68.95,-183.97 ; -68.95,-244.63 0.66,-244.63 68.95,-244.63 ; -49.25,-183.97 -49.25,-104.5 ; 68.95,-254.63 68.95,-104.5 ; 78.95,-94.5 236.76,-94.5 ; 78.95,94.5 236.76,94.5 ; 94.5,78.95 94.5,190.33 ; 98.5,108.5 98.5,256.42 ; 108.5,-98.5 317.08,-98.5 ; 108.5,98.5 317.08,98.5 ; 226.76,-94.5 226.76,-2.71 226.76,94.5 ; 233.7,157.56 157.56,157.56 98.5,98.5 ; 307.08,-98.5 307.08,2.19 307.08,98.5 ; 98.5,98.5 113.35,119 119,113.35 98.5,98.5 ; 98.5,98.5 98.5,-98.5 -98.5,-98.5 -98.5,98.5 98.5,98.5
  text "5" at -9.48,264.92 h31
  text "5" at 288.58,-9.31 h31
  text "4.8" at -41.19,198.83 h31
  text "4.8" at 208.26,-43.21 h31
  text "3.5" at -39.84,-226.13 h31
  text "0.5" at -231.63,-155.47 h31
  text "3.5" at -247.99,-38.17 h31
  text "0.5" at -175.31,132.09 h31
  text "PADS 1-32 SH_028X011S" at -160.4,-420 h31
  text "PAD  33   S142SXP" at -170.8,-475 h31
  text "(ALL PADS ROUNDED TO MILS)" at -270.89,-526.46 h31
  text "ALL DIMS IN MM" at -165.25,-303.62 h31
  text "(DIM.FOR REF.ONLY)" at -163.31,-357.94 h31
  text "QFN32_S142EP" at -121.51,344.04 h31
  text "PACKAGE" at 247.24,166.31 h31
  text "OUTLINE" at 248.18,120.02 h31
  text "17" at 116.11,-81.44 h30
  text "8" at -131.96,-98.87 h30
  text "1" at -132.67,73.49 h30
  text "16" at 71.86,-140.98 h30
  text "32" at -88.8,120.58 h30
  text "24" at 114.43,57.67 h30
  text "25" at 47.14,119.57 h30
  text "9" at -93.59,-139.11 h30
Top Courtyard:
  dashed: -74.45,-108.5 74.45,-108.5 74.45,-98.5 98.5,-98.5 98.5,-74.45 108.5,-74.45 108.5,74.45 98.5,74.45 98.5,98.5 74.45,98.5 74.45,108.5 -74.45,108.5 -74.45,98.5 -98.5,98.5 -98.5,74.45 -108.5,74.45 -108.5,-74.45 -98.5,-74.45 -98.5,-98.5 -74.45,-98.5
Top Component Center:
  lines w1: -10,0 10,0 ; 0,-10 0,10
Mechanical 15:
  text "33" at -8,0 h10
  text "24" at 86.5,68.95 h10
Mechanical 24:
  dashed: 73.93,242.07 98.93,246.07 73.93,250.07
  dashed: 69.93,175.98 94.93,179.98 69.93,183.98
  dashed: -73.07,250.07 -98.07,246.07 -73.07,242.07
  dashed: -69.07,183.98 -94.07,179.98 -69.07,175.98
  dashed: 311.51,73.15 307.51,98.15 303.52,73.15
  dashed: 231.19,69.15 227.2,94.15 223.2,69.15
  dashed: 303.52,-73.85 307.51,-98.85 311.51,-73.85
  dashed: 223.2,-69.85 227.2,-94.85 231.19,-69.85
  dashed: 44.38,-248.98 69.38,-244.98 44.38,-240.98
  dashed: -23.82,-170.32 -48.82,-174.32 -23.82,-178.31
  dashed: -43.52,-240.98 -68.52,-244.98 -43.52,-248.98
  dashed: -93.52,-178.31 -68.52,-174.32 -93.52,-170.32
  dashed: -160.37,93.6 -156.38,68.6 -152.38,93.6
  dashed: -152.38,23.91 -156.38,48.91 -160.37,23.91
  dashed: -225.06,43.6 -229.06,68.6 -233.05,43.6
  dashed: -233.05,-44.3 -229.06,-69.3 -225.06,-44.3
  lines w1: -257.44,-174.32 -68.52,-174.32 -48.82,-174.32 1.18,-174.32 ; -239.06,-69.3 -104.07,-69.3 ; -239.06,68.6 -104.07,68.6 -166.38,68.6 ; -229.06,-69.3 -229.06,1.99 -229.06,68.6 ; -166.38,48.91 -104.07,48.91 ; -156.38,-1.09 -156.38,48.91 -156.38,68.6 -156.38,238.99 ; -98.07,108.15 -98.07,256.07 ; -98.07,246.07 2.46,246.07 98.93,246.07 ; -94.07,78.6 -94.07,189.98 ; -94.07,179.98 -0.26,179.98 94.93,179.98 ; -68.52,-254.98 -68.52,-104.85 -68.52,-184.32 ; -68.52,-244.98 1.09,-244.98 69.38,-244.98 ; -48.82,-184.32 -48.82,-104.85 ; 69.38,-254.98 69.38,-104.85 ; 79.38,-94.85 237.2,-94.85 ; 79.38,94.15 237.2,94.15 ; 94.93,78.6 94.93,189.98 ; 98.93,108.15 98.93,256.07 ; 108.93,-98.85 317.51,-98.85 ; 108.93,98.15 317.51,98.15 ; 227.2,-94.85 227.2,-3.06 227.2,94.15 ; 307.51,-98.85 307.51,1.84 307.51,98.15
  text "5" at -9.04,264.57 h31
  text "4.8" at -40.76,198.48 h31
  text "5" at 289.01,-9.66 h31
  text "4.8" at 208.7,-43.56 h31
  text "3.5" at -39.41,-226.48 h31
  text "0.5" at -174.88,131.74 h31
  text "0.5" at -231.2,-155.82 h31
  text "3.5" at -247.56,-38.51 h31
  text "(ALL PADS ROUNDED TO MILS)" at -270.89,-526.46 h31
  text "(DIM.FOR REF.ONLY)" at -163.31,-357.94 h31
  text "ALL DIMS IN MM" at -165.25,-303.62 h31
  text "QFN32_S142EP" at -120.59,343.87 h31
  text "PAD  33   S142SXP" at -170.8,-475 h31
  text "PADS 1-32 SH_028X011S" at -160.4,-420 h31
Mechanical 25:
  dashed: -84.45,-118.5 -84.45,-108.5 -108.5,-108.5 -108.5,-84.45 -118.5,-84.45 -118.5,84.45 -108.5,84.45 -108.5,108.5 -84.45,108.5 -84.45,118.5 84.45,118.5 84.45,108.5 108.5,108.5 108.5,84.45 118.5,84.45 118.5,-84.45 108.5,-84.45 108.5,-108.5 84.45,-108.5 84.45,-118.5
3D body: height 150, standoff 0, extent -108.5,-108.5 108.5,108.5

## R0402 [mm]
pads (2):
  rect 0.55x0.55 smd: 1(-0.45,0) 2(0.45,0)
Top Layer keep-out:
  region: -0.127,0.381 -0.127,-0.381 0.127,-0.381 0.127,0.381
Top 3D Body:
  region: -0.889,-0.381 0.889,-0.381 0.889,0.381 -0.889,0.381
Top Assembly:
  lines w0.15: -0.25,-0.4 -0.9,-0.4 -0.9,0.4 -0.25,0.4 ; 0.25,-0.4 0.9,-0.4 0.9,0.4 0.25,0.4
  text "NC/0R" at -1.778,0.762 h0.64
Mechanical 15:
  text "1" at -0.508,-0.508 h0.64
  text "2" at 0.508,-0.508 h0.64
3D body: height 3.81, standoff 0, extent -0.889,-0.381 0.889,0.381

## R0603 [mm]
pads (2):
  rect 0.65x0.8 smd: 1(-0.725,0) 2(0.725,0)
Top Layer keep-out:
  region: -0.254,0.381 -0.254,-0.381 0.254,-0.381 0.254,0.381
Top Overlay:
Top 3D Body:
  region: -1.397,-0.635 1.397,-0.635 1.397,0.635 -1.397,0.635
Top Assembly:
  lines w0.15: -0.3,-0.6 -1.35,-0.6 -1.35,0.6 -0.3,0.6 ; 0.3,-0.6 1.35,-0.6 1.35,0.6 0.3,0.6
Mechanical 15:
  text "1" at -0.725,-0.102 h0.25
  text "2" at 0.725,-0.102 h0.25
3D body: height 3.81, standoff 0, extent -1.397,-0.635 1.397,0.635

## R1206 [mm]
pads (2):
  rect 1.4x1.6 smd: 1(-1.296,0) 2(1.304,0)
Top Layer keep-out:
  region: -0.504,0.889 -0.504,-0.889 0.512,-0.889 0.512,0.889
Top Overlay:
  lines w0.15: -1.096,-1 -2.196,-1 -2.196,1 -1.096,1 ; 1.104,-1 2.204,-1 2.204,1 1.104,1
Top 3D Body:
  region: -2.155,-1.016 2.155,-1.016 2.155,1.016 -2.155,1.016
Top Assembly:
  lines w0.15: -1.096,-1 -2.196,-1 -2.196,1 -1.096,1 ; 1.104,-1 2.204,-1 2.204,1 1.104,1
Mechanical 15:
  text "1" at -1.296,-0.102 h0.25
  text "2" at 1.304,-0.102 h0.25
3D body: height 3.81, standoff 0, extent -2.155,-1.016 2.155,1.016

## RJ45-TH_DS1129-04 [mm]
pads (28):
  round 1.27 / inner round 1.524 / far side round 1.27 hole 0.914: A1(-4.33,0.14) A2(-5.35,1.92) A3(-6.37,0.14) A4(-7.39,1.92) A5(-8.41,0.14) A6(-9.43,1.92) A7(-10.45,0.14) A8(-11.47,1.92) A9(-1.04,6.73) A10(-3.33,6.73) A11(-12.47,6.73) A12(-14.76,6.73) B1(11.42,0.14) B2(10.4,1.92) B3(9.38,0.14) B4(8.36,1.92) B5(7.34,0.14) B6(6.32,1.92) B7(5.3,0.14) B8(4.28,1.92) B9(14.71,6.73) B10(12.42,6.73) B11(3.28,6.73) B12(0.99,6.73)
  round 2.286 hole 1.803: FG1(-16.1,1.16) FG2(16.05,1.16)
  round 3.25 / inner round 1.524 / far side round 3.25 hole 3.25 unplated: NC1(14.2,-2.4) NC2(-14.25,-2.4)
Top Overlay:
  lines w0.2: -16.1,-0.2 -16.1,-7.9 16.1,-7.9 16.1,-0.2 ; -16.1,2.5 -16.1,7.9 16.1,7.9 16.1,2.5 ; -14.7,5.5 -12.4,5.5 ; -13.3,5 -13.3,6 ; -3.3,5.5 -1,5.5 ; -1.9,5 -1.9,6 ; 1,5.5 3.3,5.5 ; 2.4,5 2.4,6 ; 12.4,5.5 14.7,5.5 ; 13.8,5 13.8,6 ; -13.8,5 -13.3,5.5 -13.8,6 -13.8,5 ; -2.4,5 -1.9,5.5 -2.4,6 -2.4,5 ; 1.9,5 2.4,5.5 1.9,6 1.9,5 ; 13.3,5 13.8,5.5 13.3,6 13.3,5
Top 3D Body:
  region: -16.1,7.9 -16.1,-7.9 16.1,-7.9 16.1,7.9
Top Assembly:
  lines w0.2: -16.1,-7.9 16.1,-7.9 16.1,7.9 -16.1,7.9 -16.1,-7.9
Mechanical 15:
  text "A4" at -6.76,1.92 h0.79
  text "A5" at -7.78,0.14 h0.79
  text "B4" at 8.99,1.92 h0.79
  text "B5" at 7.97,0.14 h0.79
  text "NC1" at 15.145,-2.4 h0.79
  text "NC2" at -13.305,-2.4 h0.79
  text "FG1" at -15.155,1.16 h0.79
  text "FG2" at 16.995,1.16 h0.79
  text "A6" at -8.8,1.92 h0.79
  text "A2" at -4.72,1.92 h0.79
  text "B2" at 11.03,1.92 h0.79
  text "B3" at 10.01,0.14 h0.79
  text "B6" at 6.95,1.92 h0.79
  text "A3" at -5.74,0.14 h0.79
  text "B1" at 12.05,0.14 h0.79
  text "A1" at -3.7,0.14 h0.79
  text "A11" at -10.58,6.73 h0.79
  text "A8" at -10.84,1.92 h0.79
  text "A7" at -9.82,0.14 h0.79
  text "B7" at 5.93,0.14 h0.79
  text "B8" at 4.91,1.92 h0.79
  text "B11" at 5.17,6.73 h0.79
  text "B10" at 14.31,6.73 h0.79
  text "A10" at -1.44,6.73 h0.79
  text "A12" at -12.87,6.73 h0.79
  text "B12" at 2.88,6.73 h0.79
  text "A9" at 0.22,6.73 h0.79
  text "B9" at 15.97,6.73 h0.79
3D body: height 3.81, standoff 0, extent -16.1,-7.9 16.1,7.9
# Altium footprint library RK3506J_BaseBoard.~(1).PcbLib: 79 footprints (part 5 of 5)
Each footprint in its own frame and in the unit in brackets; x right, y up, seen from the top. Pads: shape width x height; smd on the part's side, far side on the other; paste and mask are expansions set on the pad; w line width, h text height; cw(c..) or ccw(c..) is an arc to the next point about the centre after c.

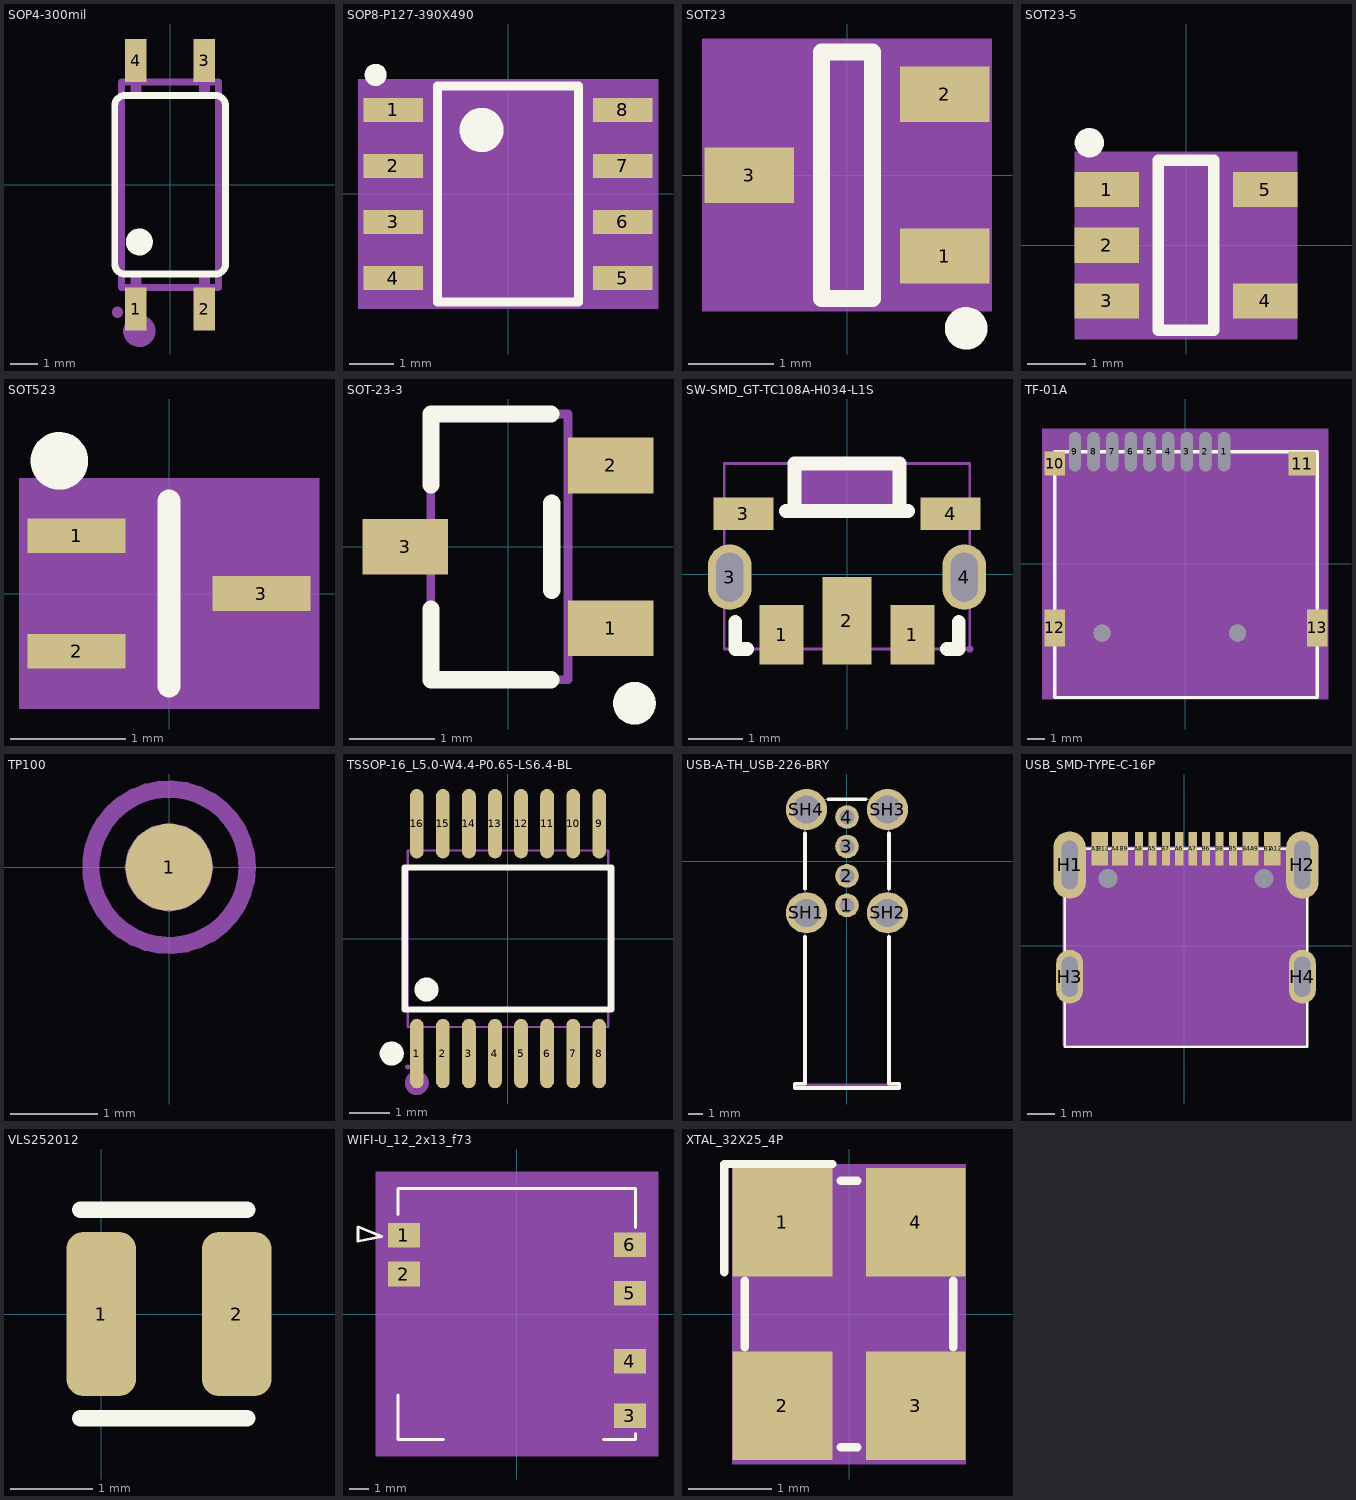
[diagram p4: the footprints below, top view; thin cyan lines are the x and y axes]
## SOP4-300mil [mm]
pads (4):
  rect 0.8x1.6 smd: 1(-1.27,-4.61) 2(1.27,-4.61) 3(1.27,4.61) 4(-1.27,4.61)
Top Overlay:
  circle w0.5: c-1.143,-2.121 r0.25
  lines w0.254: -2.057,-2.934 ccw(c-1.676,-2.934) -1.676,-3.315 1.676,-3.315 ccw(c1.676,-2.934) 2.057,-2.934 2.057,2.934 ccw(c1.676,2.934) 1.676,3.315 -1.676,3.315 ccw(c-1.676,2.934) -2.057,2.934 -2.057,-2.934
Top Component Outline:
  circle w0.6: c-1.143,-5.423 r0.3
Mechanical 15:
  region: -1.465,3.321 -1.465,3.891 -1.075,3.891 -1.075,3.321
  region: -1.465,3.881 -1.465,4.731 -1.075,4.731 -1.075,3.881
  region: 1.075,3.881 1.075,4.731 1.465,4.731 1.465,3.881
  region: 1.075,3.321 1.075,3.891 1.465,3.891 1.465,3.321
  region: -1.755,-4.731 -1.755,-4.691 -1.785,-4.618 -1.842,-4.561 -1.915,-4.531 -1.995,-4.531 -2.068,-4.561 -2.125,-4.618 -2.155,-4.691 -2.155,-4.731 -2.155,-4.771 -2.125,-4.844 -2.068,-4.901 -1.995,-4.931 -1.915,-4.931 -1.842,-4.901 -1.785,-4.844 -1.755,-4.771 -1.755,-4.731
  region: -1.465,-3.891 -1.465,-3.321 -1.075,-3.321 -1.075,-3.891
  region: -1.465,-4.731 -1.465,-3.881 -1.075,-3.881 -1.075,-4.731
  region: 1.075,-4.731 1.075,-3.881 1.465,-3.881 1.465,-4.731
  region: 1.075,-3.891 1.075,-3.321 1.465,-3.321 1.465,-3.891
  lines w0.254: -1.8,-3.81 1.8,-3.81 1.8,3.81 -1.8,3.81 -1.8,-3.81

## SOP8-P127-390X490 [mm]
pads (8):
  rect 1.35x0.55 smd: 1(-2.6,1.905) 2(-2.6,0.635) 3(-2.6,-0.635) 4(-2.6,-1.905) 5(2.6,-1.905) 6(2.6,-0.635) 7(2.6,0.635) 8(2.6,1.905)
Top Overlay:
  circle w0.5: c-0.6,1.45 r0.25
  circle w0.25: c-3,2.7 r0.125
  lines w0.2: -1.6,-2.45 1.6,-2.45 1.6,2.45 -1.6,2.45 -1.6,-2.45
Top 3D Body:
  circle w0.05: c0,0 r0.35
  region: -3.4,-2.6 -3.4,2.6 3.4,2.6 3.4,-2.6
  lines w0.05: -0.5,0 0.5,0 ; 0,-0.5 0,0.5
Top Assembly:
  circle w0.1: c-0.95,1.45 r0.5
  lines w0.1: -1.95,-2.45 1.95,-2.45 1.95,2.45 -1.95,2.45 -1.95,-2.45
Top Component Outline:
  lines w0.001: -2,-2.5 2,-2.5 2,2.5 -2,2.5 -2,-2.5
Top Courtyard:
  dashed: -3.4,-2.6 -3.4,2.6 3.4,2.6 3.4,-2.6
Mechanical 15:
  text "4" at -2.854,-1.905 h0.76
  text "3" at -2.854,-0.635 h0.76
  text "1" at -2.854,1.905 h0.76
  text "8" at 2.346,1.905 h0.76
  text "6" at 2.346,-0.635 h0.76
  text "7" at 2.346,0.635 h0.76
  text "2" at -2.854,0.635 h0.76
  text "5" at 2.346,-1.905 h0.76
3D body: height 3.81, standoff 0, extent -3.4,-2.6 3.4,2.6

## SOT23 [mm]
pads (3):
  rect 1.05x0.65 smd: 1(1.15,-0.95) 2(1.15,0.95) 3(-1.15,0)
Top Overlay:
  circle w0.25: c1.4,-1.8 r0.125
  lines w0.2: -0.3,-1.45 -0.3,1.45 0.3,1.45 0.3,-1.45 -0.3,-1.45
Top 3D Body:
  circle w0.05: c0,0 r0.35
  region: -1.7,-1.6 -1.7,1.6 1.7,1.6 1.7,-1.6
  lines w0.05: -0.5,0 0.5,0 ; 0,-0.5 0,0.5
Top Assembly:
  lines w0.1: -0.35,-1.45 0.65,-0.45 ; -0.25,-1.45 0.65,-0.55 ; -0.15,-1.45 0.65,-0.65 ; -0.05,-1.45 0.65,-0.75 ; 0.05,-1.45 0.65,-0.85 ; 0.15,-1.45 0.65,-0.95 ; 0.25,-1.45 0.65,-1.05 ; 0.35,-1.45 0.65,-1.15 ; 0.45,-1.45 0.65,-1.25 ; 0.55,-1.45 0.65,-1.35 ; -0.65,-1.45 -0.65,1.45 0.65,1.45 0.65,-1.45 -0.65,-1.45
Top Component Outline:
  lines w0.001: -0.7,-1.5 -0.7,1.5 0.7,1.5 0.7,-1.5 -0.7,-1.5
Top Courtyard:
  dashed: 1.7,-1.6 1.7,1.6 -1.7,1.6 -1.7,-1.6
Mechanical 15:
  text "1" at 0.896,-0.95 h0.76
  text "2" at 0.896,0.95 h0.76
  text "3" at -1.404,0 h0.76
3D body: height 3.81, standoff 0, extent -1.7,-1.6 1.7,1.6

## SOT23-5 [mm]
pads (5):
  rect 1.1x0.6 smd: 1(-1.35,0.95) 2(-1.35,0) 3(-1.35,-0.95) 4(1.35,-0.95) 5(1.35,0.95)
Top Overlay:
  circle w0.25: c-1.65,1.75 r0.125
  lines w0.2: -0.475,-1.45 -0.475,1.45 0.475,1.45 0.475,-1.45 -0.475,-1.45
Top 3D Body:
  circle w0.05: c0,0 r0.35
  region: 1.9,1.6 1.9,-1.6 -1.9,-1.6 -1.9,1.6
  lines w0.05: -0.5,0 0.5,0 ; 0,-0.5 0,0.5
Top Assembly:
  lines w0.1: -0.825,0.46 0.175,1.46 ; -0.825,0.56 0.075,1.46 ; -0.825,0.66 -0.025,1.46 ; -0.825,0.76 -0.125,1.46 ; -0.825,0.86 -0.225,1.46 ; -0.825,0.96 -0.325,1.46 ; -0.825,1.06 -0.425,1.46 ; -0.825,1.16 -0.525,1.46 ; -0.825,1.26 -0.625,1.46 ; -0.825,1.36 -0.725,1.46 ; -0.825,-1.46 -0.825,1.46 0.825,1.46 0.825,-1.46 -0.825,-1.46
Top Component Outline:
  lines w0.001: -0.9,-1.52 -0.9,1.52 0.9,1.52 0.9,-1.52 -0.9,-1.52
Top Courtyard:
  dashed: -1.9,1.6 -1.9,-1.6 1.9,-1.6 1.9,1.6
Mechanical 15:
  text "2" at -1.096,0 h0.76
  text "5" at 1.604,0.95 h0.76
  text "3" at -1.096,-0.95 h0.76
  text "4" at 1.604,-0.95 h0.76
  text "1" at -1.096,0.95 h0.76
3D body: height 3.81, standoff 0, extent -1.9,-1.6 1.9,1.6

## SOT523 [mm]
pads (3):
  rect 0.85x0.3 smd: 1(-0.8,0.5) 2(-0.8,-0.5) 3(0.8,0)
Top Overlay:
  circle w0.25: c-0.95,1.15 r0.125
  lines w0.2: 0,-0.8 0,0.8
Top 3D Body:
  circle w0.05: c0,0 r0.35
  region: 1.3,1 1.3,-1 -1.3,-1 -1.3,1
  lines w0.05: -0.5,0 0.5,0 ; 0,-0.5 0,0.5
Top Assembly:
  lines w0.1: -0.4,0 0.4,0.8 -0.4,0.8 -0.4,-0.8 0.4,-0.8 ; -0.4,0.1 0.3,0.8 ; -0.4,0.2 0.2,0.8 ; -0.4,0.3 0.1,0.8 ; -0.4,0.4 0,0.8 ; -0.4,0.5 -0.1,0.8 ; -0.4,0.6 -0.2,0.8 ; -0.4,0.7 -0.3,0.8
Top Component Outline:
  lines w0.001: -0.425,-0.85 -0.425,0.85 0.425,0.85 0.425,-0.85 -0.425,-0.85
Top Courtyard:
  dashed: 1.3,1 1.3,-1 -1.3,-1 -1.3,1
Mechanical 15:
  text "2" at -1.054,-0.5 h0.76
  text "1" at -1.054,0.5 h0.76
  text "3" at 0.546,0 h0.76
3D body: height 3.81, standoff 0, extent -1.3,-1 1.3,1

## SOT-23-3 [mm]
pads (3):
  rect 1x0.65 smd mask+0.051: 1(1.2,-0.95) 2(1.2,0.95) 3(-1.2,0)
Top Overlay:
  circle w0.25: c1.475,-1.825 r0.125
  lines w0.2: -0.9,-0.725 -0.9,-1.55 0.5,-1.55 ; -0.9,0.725 -0.9,1.55 0.5,1.55
  lines w0.203: 0.508,-0.508 0.508,0.508
Mechanical 13:
  lines w0.1: -0.9,-1.55 -0.9,1.55 0.7,1.55 0.7,-1.55 -0.9,-1.55

## SW-SMD_GT-TC108A-H034-L1S [mm]
pads (7):
  rect 0.8x1.09 smd paste-100 mask+0.051: 1(-1.2,-1.107) 1(1.2,-1.107)
  rect 0.9x1.6 smd paste-100 mask+0.051: 2(0,-0.852)
  oval 0.8x1.2 hole 0.5 slot 0.9 at 90 deg paste-100 mask+0.051: 3(-2.15,-0.052) 4(2.15,-0.052)
  rect 1.1x0.6 smd paste-100 mask+0.051: 3(-1.9,1.107) 4(1.9,1.107)
Top Overlay:
  lines w0.254: -2.05,-0.876 -2.05,-1.372 -1.831,-1.372 ; -1.119,1.158 0.96,1.158 ; -0.96,1.158 -0.96,2.028 0.96,2.028 0.96,1.158 ; 1.119,1.158 0.96,1.158 ; 1.831,-1.372 2.05,-1.372 2.05,-0.876
Top Paste:
  drawing of 7 lines, arcs and shapes, not listed
Top Component Outline:
  region: -0.9,2 -0.9,1.2 0.9,1.2 0.9,2
Mechanical 15:
  region: -1.45,1.007 -2.25,1.007 -2.25,1.207 -1.45,1.207
  region: 2.25,1.007 1.45,1.007 1.45,1.207 2.25,1.207
  region: -0.3,-1.352 -0.3,-0.352 0.3,-0.352 0.3,-1.352
  region: -1,-1.372 -1.4,-1.372 -1.4,-0.672 -1,-0.672
  region: 1.4,-1.372 1,-1.372 1,-0.672 1.4,-0.672
  region: 2.25,-0.403 2.05,-0.403 2.05,0.297 2.25,0.297
  region: -2.05,-0.403 -2.25,-0.403 -2.25,0.297 -2.05,0.297
  region: 2.31,-1.372 2.31,-1.397 2.275,-1.432 2.225,-1.432 2.19,-1.397 2.19,-1.372 2.19,-1.348 2.225,-1.312 2.275,-1.312 2.31,-1.348 2.31,-1.372
  lines w0.051: -2.25,-1.372 2.25,-1.372 2.25,2.028 -2.25,2.028 -2.25,-1.372

## TF-01A [mm]
pads (15):
  oval 0.7x2.3 smd: 1(2.285,6.625) 2(1.185,6.625) 3(0.085,6.625) 4(-1.015,6.625) 5(-2.115,6.625) 6(-3.215,6.625) 7(-4.315,6.625) 8(-5.415,6.625) 9(-6.515,6.625)
  rect 1.2x1.4 smd: 10(-7.715,5.925)
  rect 1.6x1.4 smd: 11(6.885,5.925)
  rect 1.2x2.2 smd: 12(-7.715,-3.775) 13(7.785,-3.775)
  round 1 hole 1: ""(-4.915,-4.075) ""(3.085,-4.075)
Top Overlay:
  lines w0.2: -7.715,-7.875 -7.715,6.625 7.785,6.625 7.785,-7.875 -7.715,-7.875
Top 3D Body:
  region: -8.435,-7.975 8.435,-7.975 8.435,7.975 -8.435,7.975
Top Assembly:
  lines w0.2: -7.715,-7.875 -7.715,6.625 7.785,6.625 7.785,-7.875 -7.715,-7.875
Mechanical 15:
  text "5" at -1.875,6.625 h0.6
  text "9" at -6.275,6.625 h0.6
  text "8" at -5.175,6.625 h0.6
  text "3" at 0.325,6.625 h0.6
  text "7" at -4.075,6.625 h0.6
  text "2" at 1.425,6.625 h0.6
  text "4" at -0.775,6.625 h0.6
  text "1" at 2.525,6.625 h0.6
  text "6" at -2.975,6.625 h0.6
  text "11" at 7.365,5.925 h0.6
  text "10" at -7.235,5.925 h0.6
  text "13" at 8.265,-3.775 h0.6
  text "12" at -7.235,-3.775 h0.6
3D body: height 3.81, standoff 0, extent -8.435,-7.975 8.435,7.975

## TP100 [mm]
pads (1):
  round 1 smd: 1(0,0)
Top Overlay:
Top 3D Body:
  region: 0,0.51 -0.195,0.471 -0.36,0.36 -0.471,0.195 -0.51,0 -0.471,-0.195 -0.434,-0.251 -0.36,-0.36 -0.195,-0.471 0,-0.51 0.195,-0.471 0.36,-0.36 0.434,-0.251 0.471,-0.195 0.51,0 0.471,0.195 0.36,0.36 0.195,0.471
Top Assembly:
  circle w0.2: c0,0 r0.9
Mechanical 15:
  text "1" at 0,-0.16 h0.4
3D body: height 3.81, standoff 0, extent -0.51,-0.51 0.51,0.51

## TSSOP-16_L5.0-W4.4-P0.65-LS6.4-BL [mm]
pads (16):
  oval 0.343x1.731 smd: 1(-2.275,-2.866) 2(-1.625,-2.866) 3(-0.975,-2.866) 4(-0.325,-2.866) 5(0.325,-2.866) 6(0.975,-2.866) 7(1.625,-2.866) 8(2.275,-2.866) 9(2.275,2.866) 10(1.625,2.866) 11(0.975,2.866) 12(0.325,2.866) 13(-0.325,2.866) 14(-0.975,2.866) 15(-1.625,2.866) 16(-2.275,2.866)
Top Overlay:
  circle w0.3: c-2.899,-2.866 r0.15
  circle w0.3: c-2.032,-1.27 r0.15
  lines w0.152: -2.576,-1.771 2.576,-1.771 2.576,1.772 -2.576,1.772 -2.576,-1.771
Top Component Outline:
  circle w0.3: c-2.275,-3.6 r0.15
Mechanical 15:
  drawing of 37 lines, arcs and shapes, not listed

## USB-A-TH_USB-226-BRY [mm]
pads (8):
  round 1.6 hole 1: 1(0,-3) 2(0,-1) 3(0,1) 4(0,3)
  round 2.8 hole 1.9: SH1(-2.75,-3.5) SH2(2.75,-3.5) SH3(2.75,3.5) SH4(-2.75,3.5)
Top Overlay:
  lines w0.254: -2.85,-5.128 -2.85,-15.1 -3.55,-15.1 -3.55,-15.4 3.55,-15.4 3.55,-15.1 2.85,-15.1 2.85,-5.128 ; -2.85,-1.872 -2.85,1.872 ; -1.277,4.2 1.277,4.2 ; 2.85,-1.872 2.85,1.872
Top Component Outline:
  region: -2.97,-5.13 -2.73,-5.13 -2.73,-15.08 -2.97,-15.08
  region: 2.73,-5.13 2.97,-5.13 2.97,-15.08 2.73,-15.08
  region: -3.55,-15.09 -3.55,-15.39 3.55,-15.39 3.55,-15.09
Mechanical 15:
  region: -0.125,-2.8 0.125,-2.8 0.125,-3.2 -0.125,-3.2
  region: -0.125,-0.8 0.125,-0.8 0.125,-1.2 -0.125,-1.2
  region: -0.125,1.2 0.125,1.2 0.125,0.8 -0.125,0.8
  region: -0.125,3.2 0.125,3.2 0.125,2.8 -0.125,2.8
  region: 2.6,-2.901 2.6,-4.101 3.55,-4.101 3.55,-2.9
  region: -2.6,-4.099 -2.6,-2.899 -3.55,-2.899 -3.55,-4.1
  region: -2.6,3 -2.6,4.2 -3.55,4.2 -3.55,2.999
  region: 2.6,4.2 2.6,3 3.55,3 3.55,4.201
  region: -2.9,3 -2.9,4.2 -2.6,4.2 -2.6,3
  region: -2.9,-4.1 -2.9,-2.9 -2.6,-2.9 -2.6,-4.1
  region: 2.6,-4.1 2.6,-2.9 2.9,-2.9 2.9,-4.1
  region: 2.6,3 2.6,4.2 2.9,4.2 2.9,3
  region: 3.61,-15.4 3.61,-15.375 3.575,-15.34 3.525,-15.34 3.49,-15.375 3.49,-15.4 3.49,-15.425 3.525,-15.46 3.575,-15.46 3.61,-15.425 3.61,-15.4
  lines w0.051: -3.55,-15.4 -3.55,-15.1 -2.85,-15.1 -2.85,4.2 2.85,4.2 2.85,-15.1 3.55,-15.1 3.55,-15.4 -3.55,-15.4

## USB_SMD-TYPE-C-16P [mm]
pads (22):
  rect 0.3x1.25 smd: A1(-3.287,3.607) A4(-2.536,3.607) A5(-1.187,3.607) A6(-0.187,3.607) A7(0.314,3.607) A8(-1.687,3.607) A9(2.614,3.607) A12(3.414,3.607) B1(3.114,3.607) B4(2.314,3.607) B5(1.814,3.607) B6(0.814,3.607) B7(-0.687,3.607) B8(1.314,3.607) B9(-2.236,3.607) B12(-2.987,3.607)
  oval 1.2x2.5 hole 1.8 slot 0.6 at 0 deg: H1(-4.257,3.007) H2(4.384,3.007)
  oval 1x2 hole 1.5 slot 0.6 at 0 deg: H3(-4.257,-1.143) H4(4.384,-1.143)
  round 0 / inner round 0 / far side round 0.711 hole 0.711 unplated: NC1(-2.827,2.507) NC2(2.954,2.507)
Top Overlay:
  lines w0.1: -4.436,-3.743 -4.436,3.607 4.563,3.607 4.563,-3.743 -4.436,-3.743
Top 3D Body:
  region: -4.508,3.683 -4.508,-3.683 4.508,-3.683 4.508,3.683
Top Assembly:
Mechanical 15:
  text "B12" at -1.767,3.607 h0.51
  text "A1" at -2.474,3.607 h0.51
  text "B1" at 3.926,3.607 h0.51
  text "A12" at 4.633,3.607 h0.51
  text "H2" at 5.196,3.007 h0.51
  text "H4" at 5.196,-1.143 h0.51
  text "H1" at -3.444,3.007 h0.51
  text "H3" at -3.444,-1.143 h0.51
  text "B8" at 2.126,3.607 h0.51
  text "A8" at -0.874,3.607 h0.51
  text "NC2" at 4.173,2.507 h0.51
  text "NC1" at -1.607,2.507 h0.51
  text "B6" at 1.626,3.607 h0.51
  text "A6" at 0.626,3.607 h0.51
  text "B4" at 3.126,3.607 h0.51
  text "A9" at 3.426,3.607 h0.51
  text "A4" at -1.724,3.607 h0.51
  text "B9" at -1.424,3.607 h0.51
  text "A7" at 1.126,3.607 h0.51
  text "B7" at 0.126,3.607 h0.51
  text "B5" at 2.626,3.607 h0.51
  text "A5" at -0.374,3.607 h0.51
3D body: height 3.81, standoff 0, extent -4.508,-3.683 4.508,3.683

## VLS252012 [mm]
pads (2):
  rrect50% 0.85x2 smd: 1(0,0) 2(1.65,0)
Top Overlay:
  lines w0.203: -0.254,-1.27 1.778,-1.27 ; -0.254,1.27 1.778,1.27
Mechanical 14:
  text "'.Designator'" at -1.034,-0.541 h0.75

## WIFI-U_12_2x13_f73 [mil]
pads (6):
  rect 65x50 smd: 1(-228.36,159.45) 2(-228.36,80.71) 3(228.36,-205.91) 4(228.36,-95.67) 5(228.36,42.13) 6(228.36,139.76)
Top Overlay:
  lines w6: -239.96,-164.17 -239.96,-253.94 -148.43,-253.94 ; -239.96,201.18 -239.96,253.94 239.96,253.94 239.96,175.2 ; 175.2,-253.94 239.96,-253.94 239.96,-241.34 ; -321.2,147.08 -273.17,156.92 -321.2,176.21 -321.2,147.08
Top 3D Body:
  region: -285.24,-287.99 -285.24,287.99 285.24,287.99 285.24,-287.99
Top Assembly:
  lines w6: -239.96,-253.94 -239.96,253.94 239.96,253.94 239.96,-253.94 -239.96,-253.94
Mechanical 15:
  text "1" at -220.36,159.45 h20
  text "6" at 236.36,139.76 h20
  text "3" at 236.36,-205.91 h20
  text "4" at 236.36,-95.67 h20
  text "5" at 236.36,42.13 h20
  text "2" at -220.36,80.71 h20
3D body: height 150, standoff 0, extent -285.24,-287.99 285.24,287.99

## XTAL_32X25_4P [mm]
pads (4):
  rect 1.2x1.3 smd: 1(-0.8,1.1) 2(-0.8,-1.1) 3(0.8,-1.1) 4(0.8,1.1)
Top Overlay:
  lines w0.1: -1.5,0.5 -1.5,1.8 -0.2,1.8 ; -1.25,-0.4 -1.25,0.4 ; -0.1,-1.6 0.1,-1.6 ; -0.1,1.6 0.1,1.6 ; 1.25,-0.4 1.25,0.4
Top 3D Body:
  circle w0.05: c0,0 r0.35
  region: -1.4,1.8 -1.4,-1.8 1.4,-1.8 1.4,1.8
  lines w0.05: -0.5,0 0.5,0 ; 0,-0.5 0,0.5
Top Assembly:
  lines w0.1: -1.25,0.6 -0.25,1.6 ; -1.25,0.7 -0.35,1.6 ; -1.25,0.8 -0.45,1.6 ; -1.25,0.9 -0.55,1.6 ; -1.25,1 -0.65,1.6 ; -1.25,1.1 -0.75,1.6 ; -1.25,1.2 -0.85,1.6 ; -1.25,1.3 -0.95,1.6 ; -1.25,1.4 -1.05,1.6 ; -1.25,1.5 -1.15,1.6 ; -1.25,-1.6 1.25,-1.6 1.25,1.6 -1.25,1.6 -1.25,-1.6
Top Component Outline:
  lines w0.001: -1.35,-1.7 1.35,-1.7 1.35,1.7 -1.35,1.7 -1.35,-1.7
Mechanical 15:
  text "1" at -0.8,0.846 h0.76
  text "3" at 0.8,-1.354 h0.76
  text "2" at -0.8,-1.354 h0.76
  text "4" at 0.8,0.846 h0.76
3D body: height 3.81, standoff 0, extent -1.4,-1.8 1.4,1.8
